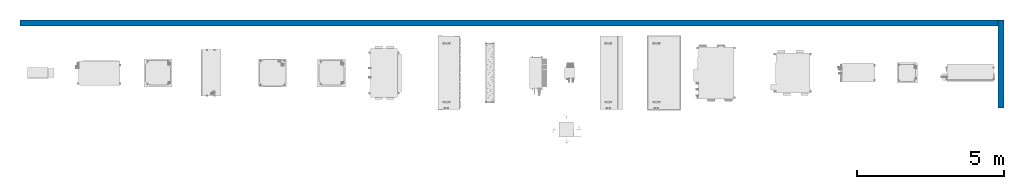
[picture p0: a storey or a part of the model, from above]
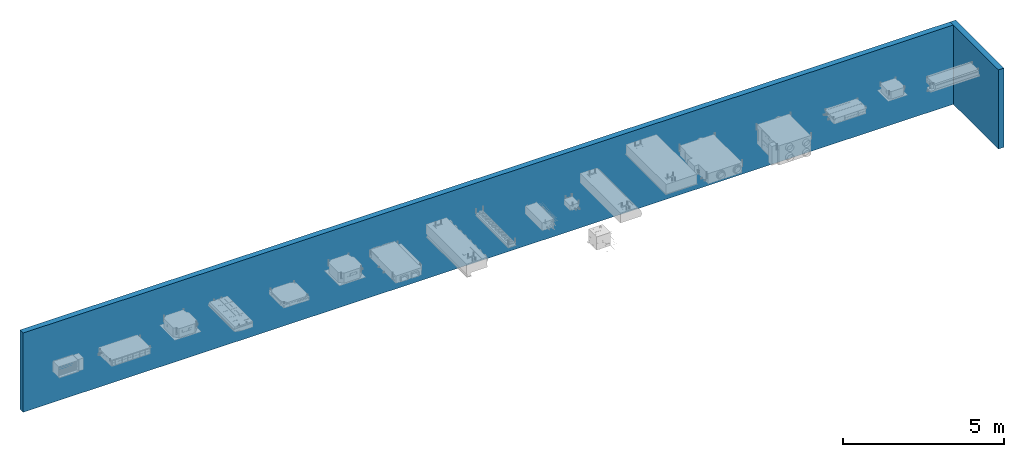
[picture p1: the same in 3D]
Properties of the parts of a building model (IFC2X3), part 1 of 3

# File
Description: ViewDefinition [CoordinationView_V2.0]
Time: 2023-03-29T12:23:49
Written by: The EXPRESS Data Manager Version 5.02.0100.07 : 28 Aug 2013
Made in: 20220224_1700(x64) - Exporter 19.2.60.3 - Default UI
Comment: STEP Physical File produced by: The EXPRESS Data Manager Version 5.02.0100.07 : 28 Aug 2013 * Module: EDMstepFileFactory/EDMstandAlone * Creation date: Wed Mar 29 12:23:49 2023 * Host: DESKTOP-IHH7OF8 * Database: C:\Users\BMP_02\AppData\Local\Temp\{4DC32F8F-CF9E-48E4-9B4F-A92181148DC5}\ifc * Database version: 5507 * Database creation date: Wed Mar 29 12:23:40 2023 * Schema: IFC2X3 * Model: DataRepository.ifc * Model creation date: Wed Mar 29 12:23:41 2023 * Header model: DataRepository.ifc_HeaderModel * Header model creation date: Wed Mar 29 12:23:41 2023 * EDMuser: sdai-user * EDMgroup: sdai-group * License ID and type: 5605 : Permanent license. Expiry date: * EDMstepFileFactory options: 020000

# IfcSite, Default
RefLatitude: 42, 24, 53, 508911; RefLongitude: -71, -15, -29, -58837; RefElevation: 0 mm
Other - Category: Project Information

# IfcBuilding
Pset_BuildingCommon - NumberOfStoreys: 1
Other - Category: Project Information

# IfcBuildingStorey, Level 1
LongName: Level 1; Elevation: 0 mm
Other(Type) - Category: Levels; Family Name: Level
Identity Data(Type) - Type Name: Level 1
Graphics(Type) - Color: 0; Line Pattern: Solid; Line Weight: 1; Symbol at End 1 Default: no; Symbol at End 2 Default: yes
Constraints(Type) - Elevation Base: Project Base Point
Constraints - Elevation: 0 mm
Dimensions - Computation Height: 0 mm
Identity Data - Structural: no; Building Story: yes; Name: Level 1
Other - Category: Levels; Family: Level: Level 1; Family and Type: Level: Level 1; Type: Level: Level 1; Type Id: Level: Level 1

# IfcBuildingElementProxy: reference geometry_gen, RSen_00_GM_FB_reference geometry_gen_witas:reference geometry_gen:1185629
In: Level 1
Type - Material: RSen_x_rgb 255 128 128 T80 red_gen, RSen_x_rgb 255 0 0 T00 red_gen, RSen_x_rgb 255 255 255 T00 pure white_gen, RSen_x_rgb 000 000 000 T00 black_gen, RSen_x_rgb 021 107 182 T00 blue_gen, RSen_x_rgb 000 128 000 T80 green_gen
Type - Constraints - Default Elevation: 0 mm; WT_H Reference_angled wall mounted: angled wall mounted_gen; WT_H Reference_parallel wall mounted: parallel wall mounted_gen; WT_H Reference_pendant - horizontal mounted: pendant - horizontal mounted_gen; WT_H Reference_pendant - vertical mounted: pendant - vertical mounted_gen; WT_H Reference_recessed: recessed_gen; WT_H Reference_wall mounted: wall mounted_gen
Type - Identity Data - Type Name: reference geometry_gen; WT_I Coding: V4.0; WT_I Interface: V4.0
Type - Other - Category: Generic Models; Family Name: RSen_00_GM_FB_reference geometry_gen_witas
Type - Text - 250: 250 mm; WT_I Revit manual: http://revit-mep-be-localiser.blogspot.com/2010/01/referentiebalk.html
Pset_BuildingElementProxyCommon - Reference: reference geometry_gen
Constraints - Elevation: 2500 mm; Host: Reference Plane : ceiling; Level: Level: Level 1; WT_H Depth 1: 500 mm; WT_H Depth 2: 10000 mm; WT_H Half height: 250 mm; WT_H Half height_negative: -250 mm; WT_H Half length: 250 mm; WT_H Half length_negative: -250 mm; WT_H Height: 500 mm; WT_H Length: 500 mm; WT_H Reference_type: pendant - horizontal mounted_gen; WT_H Suspension: yes; WT_H Suspension_height: 1 mm; WT_H X coordinate in plane: 0 mm; WT_H Y coordinate in plane: 0 mm
Construction - WT_V Angled wall mounted: no; WT_V Parallel wall mounted: no; WT_V Pendant - horizontal mounted: yes; WT_V Pendant - vertical mounted: no; WT_V Plane: 1; WT_V Recess depth: 0 mm; WT_V Recessed: no; WT_V Rotation about axis: 0 deg; WT_V Surface mounted: no; WT_V Suspension_height: 0 mm; WT_V X coordinate in plane: 0 mm; WT_V Y coordinate in plane: 0 mm; WT_V Z coordinate in plane: 0.1 mm
Dimensions - Area: 2.52812 m2; Volume: 0.375224 m3
Graphics - Mark: no
Other - Family: RSen_00_GM_FB_reference geometry_gen_witas: reference geometry_gen; Family and Type: RSen_00_GM_FB_reference geometry_gen_witas: reference geometry_gen; Schedule Level: Level: Level 1; Type: RSen_00_GM_FB_reference geometry_gen_witas: reference geometry_gen; Type Id: RSen_00_GM_FB_reference geometry_gen_witas: reference geometry_gen
Phasing - Phase Created: New Construction
Text - Dim_01: L; Dim_02: H; Dim_03: W

# IfcBuildingElementProxy: standard, RSen_57_ME_FB_SOg - alb02rbsnadbt00 - SH_daikin_tbq:standard:1750593
In: Level 1
Type - Material: RSen_n6_PE_black, RSen_x_rgb 199 235 223 T00 galvanised steel plate_gen
Type - Constraints - Default Elevation: 1219.2 mm; TBQ SOg: yes
Type - Dimensions - TBQ Height: 292 mm; TBQ Length: 1820 mm; TBQ Width: 920 mm
Type - Identity Data - Manufacturer: Daikin Europe N.V.; Type Name: standard
Type - Materials and Finishes - TBQ Material 01: RSen_x_rgb 199 235 223 T00 galvanised steel plate_gen; TBQ Material 02: RSen_n6_PE_black
Type - Other - Category: Mechanical Equipment; Family Name: RSen_57_ME_FB_SOg - alb02rbsnadbt00 - SH_daikin_tbq
Pset_BuildingElementProxyCommon - Reference: standard
Pset_ManufacturerTypeInformation - Manufacturer: Daikin Europe N.V.
Constraints - Moves With Nearby Elements: no
Dimensions - Area: 5.74131 m2; Volume: 0.510282 m3
Identity Data - Mark: 113
Other - Family: RSen_57_ME_FB_SOg - alb02rbsnadbt00 - SH_daikin_tbq: standard; Family and Type: RSen_57_ME_FB_SOg - alb02rbsnadbt00 - SH_daikin_tbq: standard; Type: RSen_57_ME_FB_SOg - alb02rbsnadbt00 - SH_daikin_tbq: standard; Type Id: RSen_57_ME_FB_SOg - alb02rbsnadbt00 - SH_daikin_tbq: standard
Phasing - Phase Created: New Construction

# IfcBuildingElementProxy: standard, RSen_57_DUA_FB_SOg - ald07hefbu00 - SH_daikin_tbq:standard:2526252
In: Level 1
Type - Material: RSen_x_rgb 000 000 000 T00 black_gen, RSen_x_rgb 195 195 195 T00 silver_gen
Type - Constraints - Default Elevation: 1219.2 mm; TBQ SOg: yes
Type - Dimensions - TBQ Depth: 440 mm; TBQ Height: 740 mm; TBQ Length: 370 mm
Type - Identity Data - Manufacturer: Daikin Europe N.V.; Type Name: standard
Type - Materials and Finishes - TBQ Material 01: RSen_x_rgb 195 195 195 T00 silver_gen; TBQ Material 02: RSen_x_rgb 000 000 000 T00 black_gen
Type - Other - Category: Duct Accessories; Family Name: RSen_57_DUA_FB_SOg - ald07hefbu00 - SH_daikin_tbq
Pset_BuildingElementProxyCommon - Reference: standard
Pset_ManufacturerTypeInformation - Manufacturer: Daikin Europe N.V.
Constraints - Moves With Nearby Elements: no
Dimensions - Area: 1.96556 m2; Volume: 0.031201 m3
Identity Data - Mark: 3
Insulation - Insulation Thickness: 0 mm
Lining - Lining Thickness: 0 mm
Other - Family: RSen_57_DUA_FB_SOg - ald07hefbu00 - SH_daikin_tbq: standard; Family and Type: RSen_57_DUA_FB_SOg - ald07hefbu00 - SH_daikin_tbq: standard; Type: RSen_57_DUA_FB_SOg - ald07hefbu00 - SH_daikin_tbq: standard; Type Id: RSen_57_DUA_FB_SOg - ald07hefbu00 - SH_daikin_tbq: standard
Phasing - Phase Created: New Construction

# IfcBuildingElementProxy: standard, RSen_55_ME_FB_SOg - fha140aveb - SH_daikin_tbq:standard:2197211
In: Level 1
Type - Material: RSen_x_rgb 055 053 053 T00 gray_gen, RSen_x_rgb 0 0 0 T30 aluminium rectangular canvas_gen, RSen_x_rgb 255 255 255 T00 pure white_gen
Type - Constraints - Default Elevation: 1219.2 mm; TBQ SOg: yes
Type - Dimensions - TBQ Height: 235 mm; TBQ Length: 1590 mm; TBQ Width: 690 mm
Type - Identity Data - Manufacturer: Daikin Europe N.V.; Type Name: standard
Type - Materials and Finishes - TBQ Material 01: RSen_x_rgb 255 255 255 T00 pure white_gen; TBQ Material 02: RSen_x_rgb 0 0 0 T30 aluminium rectangular canvas_gen
Type - Other - Category: Mechanical Equipment; Family Name: RSen_55_ME_FB_SOg - fha140aveb - SH_daikin_tbq
Pset_BuildingElementProxyCommon - Reference: standard
Pset_ManufacturerTypeInformation - Manufacturer: Daikin Europe N.V.
Constraints - Moves With Nearby Elements: no
Dimensions - Area: 2.86119 m2; Volume: 0.144938 m3
Identity Data - Mark: 134
Other - Family: RSen_55_ME_FB_SOg - fha140aveb - SH_daikin_tbq: standard; Family and Type: RSen_55_ME_FB_SOg - fha140aveb - SH_daikin_tbq: standard; Type: RSen_55_ME_FB_SOg - fha140aveb - SH_daikin_tbq: standard; Type Id: RSen_55_ME_FB_SOg - fha140aveb - SH_daikin_tbq: standard
Phasing - Phase Created: New Construction

# IfcBuildingElementProxy: standard, RSen_55_ME_FB_SOg - fcahg71gveb - auto-cleaning panel - SH_daikin_tbq:standard:2167862
In: Level 1
Type - Material: RSen_x_rgb 055 053 053 T00 gray_gen, RSen_x_rgb 244 244 244 T00 aluminium_gen, RSen_x_rgb 255 255 255 T00 pure white_gen
Type - Constraints - Default Elevation: 1219.2 mm; TBQ SOg: yes
Type - Dimensions - TBQ Height: 418 mm; TBQ Length: 950 mm; TBQ Width: 950 mm
Type - Identity Data - Manufacturer: Daikin Europe N.V.; Type Name: standard
Type - Materials and Finishes - TBQ Material 01: RSen_x_rgb 255 255 255 T00 pure white_gen; TBQ Material 02: RSen_x_rgb 244 244 244 T00 aluminium_gen
Type - Other - Category: Mechanical Equipment; Family Name: RSen_55_ME_FB_SOg - fcahg71gveb - auto-cleaning panel - SH_daikin_tbq
Pset_BuildingElementProxyCommon - Reference: standard
Pset_ManufacturerTypeInformation - Manufacturer: Daikin Europe N.V.
Constraints - Moves With Nearby Elements: no
Dimensions - Area: 3.08485 m2; Volume: 0.275474 m3
Identity Data - Mark: 130
Other - Family: RSen_55_ME_FB_SOg - fcahg71gveb - auto-cleaning panel - SH_daikin_tbq: standard; Family and Type: RSen_55_ME_FB_SOg - fcahg71gveb - auto-cleaning panel - SH_daikin_tbq: standard; Type: RSen_55_ME_FB_SOg - fcahg71gveb - auto-cleaning panel - SH_daikin_tbq: standard; Type Id: RSen_55_ME_FB_SOg - fcahg71gveb - auto-cleaning panel - SH_daikin_tbq: standard
Phasing - Phase Created: New Construction

# IfcBuildingElementProxy: standard, RSen_55_ME_FB_SOg - fua71aveb - SH_daikin_tbq:standard:2197208
In: Level 1
Type - Material: RSen_x_rgb 055 053 053 T00 gray_gen, RSen_x_rgb 244 244 244 T00 signal white_gen
Type - Constraints - Default Elevation: 1219.2 mm; TBQ SOg: yes
Type - Dimensions - TBQ Height: 198 mm; TBQ Length: 950 mm; TBQ Width: 950 mm
Type - Identity Data - Manufacturer: Daikin Europe N.V.; Type Name: standard
Type - Materials and Finishes - TBQ Material_01: RSen_x_rgb 244 244 244 T00 signal white_gen
Type - Other - Category: Mechanical Equipment; Family Name: RSen_55_ME_FB_SOg - fua71aveb - SH_daikin_tbq
Pset_BuildingElementProxyCommon - Reference: standard
Pset_ManufacturerTypeInformation - Manufacturer: Daikin Europe N.V.
Constraints - Moves With Nearby Elements: no
Dimensions - Area: 1.64605 m2; Volume: 0.159636 m3
Identity Data - Mark: 133
Other - Family: RSen_55_ME_FB_SOg - fua71aveb - SH_daikin_tbq: standard; Family and Type: RSen_55_ME_FB_SOg - fua71aveb - SH_daikin_tbq: standard; Type: RSen_55_ME_FB_SOg - fua71aveb - SH_daikin_tbq: standard; Type Id: RSen_55_ME_FB_SOg - fua71aveb - SH_daikin_tbq: standard
Phasing - Phase Created: New Construction

# IfcBuildingElementProxy: standard, RSen_55_ME_FB_SOg - fxfn112a2veb - designer panel - SH_daikin_tbq:standard:2414036
In: Level 1
Type - Material: RSen_x_rgb 055 053 053 T00 gray_gen, RSen_x_rgb 255 255 255 T00 pure white_gen, RSen_x_rgb 244 244 244 T00 aluminium_gen
Type - Constraints - Default Elevation: 1219.2 mm; TBQ SOg: yes
Type - Dimensions - TBQ Height: 385 mm; TBQ Length: 950 mm; TBQ Width: 950 mm
Type - Identity Data - Manufacturer: Daikin Europe N.V.; Type Name: standard
Type - Materials and Finishes - TBQ Material 01: RSen_x_rgb 255 255 255 T00 pure white_gen; TBQ Material 02: RSen_x_rgb 244 244 244 T00 aluminium_gen
Type - Other - Category: Mechanical Equipment; Family Name: RSen_55_ME_FB_SOg - fxfn112a2veb - designer panel - SH_daikin_tbq
Pset_BuildingElementProxyCommon - Reference: standard
Pset_ManufacturerTypeInformation - Manufacturer: Daikin Europe N.V.
Constraints - Moves With Nearby Elements: no
Dimensions - Area: 3.19227 m2; Volume: 0.235009 m3
Identity Data - Mark: 157
Other - Family: RSen_55_ME_FB_SOg - fxfn112a2veb - designer panel - SH_daikin_tbq: standard; Family and Type: RSen_55_ME_FB_SOg - fxfn112a2veb - designer panel - SH_daikin_tbq: standard; Type: RSen_55_ME_FB_SOg - fxfn112a2veb - designer panel - SH_daikin_tbq: standard; Type Id: RSen_55_ME_FB_SOg - fxfn112a2veb - designer panel - SH_daikin_tbq: standard
Phasing - Phase Created: New Construction

# IfcBuildingElementProxy: standard, RSen_57_ME_FB_SOg - cyvl250dk250csc - SH_daikin_tbq:standard:1401916
In: Level 1
Type - Material: RSen_x_rgb 165 165 165 T00 white aluminium_gen, RSen_x_rgb 0 0 0 T30 aluminium rectangular canvas_gen
Type - Constraints - Default Elevation: 1219.2 mm; TBQ SOg: yes
Type - Dimensions - TBQ Height: 370 mm; TBQ Length: 2500 mm; TBQ Width: 1105 mm
Type - Identity Data - Manufacturer: Daikin Europe N.V.; Type Name: standard
Type - Materials and Finishes - TBQ Material 01: RSen_x_rgb 165 165 165 T00 white aluminium_gen; TBQ Material 02: RSen_x_rgb 80 80 80 T00 aluminium canvas_gen; TBQ Material 03: RSen_x_rgb 0 0 0 T30 aluminium rectangular canvas_gen
Type - Other - Category: Mechanical Equipment; Family Name: RSen_57_ME_FB_SOg - cyvl250dk250csc - SH_daikin_tbq
Pset_BuildingElementProxyCommon - Reference: standard
Pset_ManufacturerTypeInformation - Manufacturer: Daikin Europe N.V.
Constraints - Moves With Nearby Elements: no
Dimensions - Area: 8.4651 m2; Volume: 0.933752 m3
Identity Data - Mark: 80
Other - Family: RSen_57_ME_FB_SOg - cyvl250dk250csc - SH_daikin_tbq: standard; Family and Type: RSen_57_ME_FB_SOg - cyvl250dk250csc - SH_daikin_tbq: standard; Type: RSen_57_ME_FB_SOg - cyvl250dk250csc - SH_daikin_tbq: standard; Type Id: RSen_57_ME_FB_SOg - cyvl250dk250csc - SH_daikin_tbq: standard
Phasing - Phase Created: New Construction

# IfcBuildingElementProxy: standard, RSen_55_ME_FB_SOg - bs1q25a7v1b - SH_daikin_tbq:standard:1640164
In: Level 1
Type - Material: RSen_x_rgb 199 235 223 T00 galvanised steel plate_gen
Type - Constraints - Default Elevation: 1219.2 mm; TBQ SOg: yes
Type - Dimensions - TBQ Height: 207 mm; TBQ Length: 388 mm; TBQ Width: 326 mm
Type - Identity Data - Manufacturer: Daikin Europe N.V.; Type Name: standard
Type - Materials and Finishes - TBQ Material: RSen_x_rgb 199 235 223 T00 galvanised steel plate_gen
Type - Other - Category: Mechanical Equipment; Family Name: RSen_55_ME_FB_SOg - bs1q25a7v1b - SH_daikin_tbq
Pset_BuildingElementProxyCommon - Reference: standard
Pset_ManufacturerTypeInformation - Manufacturer: Daikin Europe N.V.
Constraints - Moves With Nearby Elements: no
Dimensions - Area: 0.406695 m2; Volume: 0.0254043 m3
Identity Data - Mark: 108
Other - Family: RSen_55_ME_FB_SOg - bs1q25a7v1b - SH_daikin_tbq: standard; Family and Type: RSen_55_ME_FB_SOg - bs1q25a7v1b - SH_daikin_tbq: standard; Type: RSen_55_ME_FB_SOg - bs1q25a7v1b - SH_daikin_tbq: standard; Type Id: RSen_55_ME_FB_SOg - bs1q25a7v1b - SH_daikin_tbq: standard
Phasing - Phase Created: New Construction

# IfcBuildingElementProxy: standard, RSen_55_ME_FB_SOg - bs16q14av1b - SH_daikin_tbq:standard:1639782
In: Level 1
Type - Material: RSen_x_rgb 199 235 223 T00 galvanised steel plate_gen, RSen_n6_PE_black
Type - Constraints - Default Elevation: 1219.2 mm; TBQ SOg: yes
Type - Dimensions - TBQ Height: 298 mm; TBQ Length: 1060 mm; TBQ Width: 430 mm
Type - Identity Data - Manufacturer: Daikin Europe N.V.; Type Name: standard
Type - Materials and Finishes - TBQ Material 01: RSen_x_rgb 199 235 223 T00 galvanised steel plate_gen; TBQ Material 02: RSen_n6_PE_black
Type - Other - Category: Mechanical Equipment; Family Name: RSen_55_ME_FB_SOg - bs16q14av1b - SH_daikin_tbq
Pset_BuildingElementProxyCommon - Reference: standard
Pset_ManufacturerTypeInformation - Manufacturer: Daikin Europe N.V.
Constraints - Moves With Nearby Elements: no
Dimensions - Area: 2.23692 m2; Volume: 0.138375 m3
Identity Data - Mark: 107
Other - Family: RSen_55_ME_FB_SOg - bs16q14av1b - SH_daikin_tbq: standard; Family and Type: RSen_55_ME_FB_SOg - bs16q14av1b - SH_daikin_tbq: standard; Type: RSen_55_ME_FB_SOg - bs16q14av1b - SH_daikin_tbq: standard; Type Id: RSen_55_ME_FB_SOg - bs16q14av1b - SH_daikin_tbq: standard
Phasing - Phase Created: New Construction

# IfcBuildingElementProxy: standard, RSen_57_ME_FB_SOg - vkm100gbmv1 - SH_daikin_tbq:standard:1596971
In: Level 1
Type - Material: RSen_x_rgb 199 235 223 T00 galvanised steel plate_gen, RSen_n6_PE_black
Type - Constraints - Default Elevation: 1219.2 mm; TBQ SOg: yes
Type - Dimensions - TBQ Height: 387 mm; TBQ Length: 1764 mm; TBQ Width: 1214 mm
Type - Identity Data - Manufacturer: Daikin Europe N.V.; Type Name: standard
Type - Materials and Finishes - TBQ Material 01: RSen_x_rgb 199 235 223 T00 galvanised steel plate_gen; TBQ Material 02: RSen_n6_PE_black
Type - Other - Category: Mechanical Equipment; Family Name: RSen_57_ME_FB_SOg - vkm100gbmv1 - SH_daikin_tbq
Pset_BuildingElementProxyCommon - Reference: standard
Pset_ManufacturerTypeInformation - Manufacturer: Daikin Europe N.V.
Constraints - Moves With Nearby Elements: no
Dimensions - Area: 4.55629 m2; Volume: 0.860185 m3
Identity Data - Mark: 106
Other - Family: RSen_57_ME_FB_SOg - vkm100gbmv1 - SH_daikin_tbq: standard; Family and Type: RSen_57_ME_FB_SOg - vkm100gbmv1 - SH_daikin_tbq: standard; Type: RSen_57_ME_FB_SOg - vkm100gbmv1 - SH_daikin_tbq: standard; Type Id: RSen_57_ME_FB_SOg - vkm100gbmv1 - SH_daikin_tbq: standard
Phasing - Phase Created: New Construction

# IfcBuildingElementProxy: standard, RSen_57_ME_FB_SOg - vam1500j8veb - SH_daikin_tbq:standard:1594922
In: Level 1
Type - Material: RSen_x_rgb 199 235 223 T00 galvanised steel plate_gen, RSen_n6_PE_black
Type - Constraints - Default Elevation: 1219.2 mm; TBQ SOg: yes
Type - Dimensions - TBQ Height: 731 mm; TBQ Length: 1354 mm; TBQ Width: 1170 mm
Type - Identity Data - Manufacturer: Daikin Europe N.V.; Type Name: standard
Type - Materials and Finishes - TBQ Material 01: RSen_x_rgb 199 235 223 T00 galvanised steel plate_gen; TBQ Material 02: RSen_n6_PE_black
Type - Other - Category: Mechanical Equipment; Family Name: RSen_57_ME_FB_SOg - vam1500j8veb - SH_daikin_tbq
Pset_BuildingElementProxyCommon - Reference: standard
Pset_ManufacturerTypeInformation - Manufacturer: Daikin Europe N.V.
Constraints - Moves With Nearby Elements: no
Dimensions - Area: 9.30397 m2; Volume: 1.84505 m3
Identity Data - Mark: 105
Other - Family: RSen_57_ME_FB_SOg - vam1500j8veb - SH_daikin_tbq: standard; Family and Type: RSen_57_ME_FB_SOg - vam1500j8veb - SH_daikin_tbq: standard; Type: RSen_57_ME_FB_SOg - vam1500j8veb - SH_daikin_tbq: standard; Type Id: RSen_57_ME_FB_SOg - vam1500j8veb - SH_daikin_tbq: standard
Phasing - Phase Created: New Construction

# IfcBuildingElementProxy: standard, RSen_55_ME_FB_SOg - fxsn112a2veb - SH_daikin_tbq:standard:2485938
In: Level 1
Type - Material: RSen_x_rgb 199 235 223 T00 galvanised steel plate_gen, RSen_n6_PE_black, RSen_x_rgb 80 80 80 T00 aluminium canvas_gen
Type - Constraints - Default Elevation: 1219.2 mm; TBQ SOg: yes
Type - Dimensions - TBQ Height: 245 mm; TBQ Length: 1400 mm; TBQ Width: 800 mm
Type - Identity Data - Manufacturer: Daikin Europe N.V.; Type Name: standard
Type - Materials and Finishes - TBQ Material 01: RSen_x_rgb 199 235 223 T00 galvanised steel plate_gen; TBQ Material 02: RSen_x_rgb 80 80 80 T00 aluminium canvas_gen; TBQ Material 03: RSen_n6_PE_black
Type - Other - Category: Mechanical Equipment; Family Name: RSen_55_ME_FB_SOg - fxsn112a2veb - SH_daikin_tbq
Pset_BuildingElementProxyCommon - Reference: standard
Pset_ManufacturerTypeInformation - Manufacturer: Daikin Europe N.V.
Constraints - Moves With Nearby Elements: no
Dimensions - Area: 3.10641 m2; Volume: 0.231292 m3
Identity Data - Mark: 159
Other - Family: RSen_55_ME_FB_SOg - fxsn112a2veb - SH_daikin_tbq: standard; Family and Type: RSen_55_ME_FB_SOg - fxsn112a2veb - SH_daikin_tbq: standard; Type: RSen_55_ME_FB_SOg - fxsn112a2veb - SH_daikin_tbq: standard; Type Id: RSen_55_ME_FB_SOg - fxsn112a2veb - SH_daikin_tbq: standard
Phasing - Phase Created: New Construction

# IfcBuildingElementProxy: standard, RSen_55_ME_FB_SOg - fwe10c5tv1b - left - SH_daikin_tbq:standard:1868414
In: Level 1
Type - Material: RSen_x_rgb 199 235 223 T00 galvanised steel plate_gen, RSen_x_rgb 80 80 80 T00 aluminium canvas_gen, RSen_n6_PE_black, RSen_x_rgb 72 45 20 T00 copper_gen
Type - Constraints - Default Elevation: 1219.2 mm; TBQ SOg: yes
Type - Dimensions - TBQ Height: 247 mm; TBQ Length: 1780 mm; TBQ Width: 590 mm
Type - Identity Data - Manufacturer: Daikin Europe N.V.; Type Name: standard
Type - Materials and Finishes - TBQ Material 01: RSen_x_rgb 199 235 223 T00 galvanised steel plate_gen; TBQ Material 02: RSen_n6_PE_black; TBQ Material 03: RSen_x_rgb 80 80 80 T00 aluminium canvas_gen; TBQ Material 04: RSen_x_rgb 72 45 20 T00 copper_gen
Type - Other - Category: Mechanical Equipment; Family Name: RSen_55_ME_FB_SOg - fwe10c5tv1b - left - SH_daikin_tbq
Pset_BuildingElementProxyCommon - Reference: standard
Pset_ManufacturerTypeInformation - Manufacturer: Daikin Europe N.V.
Constraints - Moves With Nearby Elements: no
Dimensions - Area: 2.36604 m2; Volume: 0.224428 m3
Identity Data - Mark: 120
Other - Family: RSen_55_ME_FB_SOg - fwe10c5tv1b - left - SH_daikin_tbq: standard; Family and Type: RSen_55_ME_FB_SOg - fwe10c5tv1b - left - SH_daikin_tbq: standard; Type: RSen_55_ME_FB_SOg - fwe10c5tv1b - left - SH_daikin_tbq: standard; Type Id: RSen_55_ME_FB_SOg - fwe10c5tv1b - left - SH_daikin_tbq: standard
Phasing - Phase Created: New Construction

# IfcBuildingElementProxy: standard, RSen_55_ME_FB_SOg - fdxm60f3v1b9 - SH_daikin_tbq:standard:2335656
In: Level 1
Type - Material: RSen_x_rgb 244 244 244 T00 aluminium_gen, RSen_x_rgb 80 80 80 T00 aluminium canvas_gen
Type - Constraints - Default Elevation: 1219.2 mm; TBQ SOg: yes
Type - Dimensions - TBQ Height: 200 mm; TBQ Length: 1150 mm; TBQ Width: 620 mm
Type - Identity Data - Manufacturer: Daikin Europe N.V.; Type Name: standard
Type - Materials and Finishes - TBQ Material 01: RSen_x_rgb 244 244 244 T00 aluminium_gen; TBQ Material 02: RSen_x_rgb 80 80 80 T00 aluminium canvas_gen
Type - Other - Category: Mechanical Equipment; Family Name: RSen_55_ME_FB_SOg - fdxm60f3v1b9 - SH_daikin_tbq
Pset_BuildingElementProxyCommon - Reference: standard
Pset_ManufacturerTypeInformation - Manufacturer: Daikin Europe N.V.
Constraints - Moves With Nearby Elements: no
Dimensions - Area: 2.02584 m2; Volume: 0.130002 m3
Identity Data - Mark: 141
Other - Family: RSen_55_ME_FB_SOg - fdxm60f3v1b9 - SH_daikin_tbq: standard; Family and Type: RSen_55_ME_FB_SOg - fdxm60f3v1b9 - SH_daikin_tbq: standard; Type: RSen_55_ME_FB_SOg - fdxm60f3v1b9 - SH_daikin_tbq: standard; Type Id: RSen_55_ME_FB_SOg - fdxm60f3v1b9 - SH_daikin_tbq: standard
Phasing - Phase Created: New Construction

# IfcBuildingElementProxy: standard, RSen_55_ME_FB_SOg - fwf05b5tv1b - SH_daikin_tbq:standard:2387533
In: Level 1
Type - Material: RSen_x_rgb 244 244 244 T00 signal white_gen, RSen_n6_PE_black, RSen_x_rgb 199 235 223 T00 galvanised steel plate_gen
Type - Constraints - Default Elevation: 1219.2 mm; TBQ SOg: yes
Type - Dimensions - TBQ Height: 315 mm; TBQ Length: 700 mm; TBQ Width: 700 mm
Type - Identity Data - Manufacturer: Daikin Europe N.V.; Type Name: standard
Type - Materials and Finishes - TBQ Material 01: RSen_x_rgb 244 244 244 T00 signal white_gen; TBQ Material 02: RSen_n6_PE_black; TBQ Material 03: RSen_x_rgb 199 235 223 T00 galvanised steel plate_gen
Type - Other - Category: Mechanical Equipment; Family Name: RSen_55_ME_FB_SOg - fwf05b5tv1b - SH_daikin_tbq
Pset_BuildingElementProxyCommon - Reference: standard
Pset_ManufacturerTypeInformation - Manufacturer: Daikin Europe N.V.
Constraints - Moves With Nearby Elements: no
Dimensions - Area: 1.5154 m2; Volume: 0.0992006 m3
Identity Data - Mark: 155
Other - Family: RSen_55_ME_FB_SOg - fwf05b5tv1b - SH_daikin_tbq: standard; Family and Type: RSen_55_ME_FB_SOg - fwf05b5tv1b - SH_daikin_tbq: standard; Type: RSen_55_ME_FB_SOg - fwf05b5tv1b - SH_daikin_tbq: standard; Type Id: RSen_55_ME_FB_SOg - fwf05b5tv1b - SH_daikin_tbq: standard
Phasing - Phase Created: New Construction

# IfcBuildingElementProxy: standard, RSen_57_ME_FB_SOg - cyql250dk250rbn - SH_daikin_tbq:standard:1429487
In: Level 1
Type - Material: RSen_x_rgb 255 255 255 T00 pure white_gen, RSen_x_rgb 0 0 0 T30 aluminium rectangular canvas_gen
Type - Constraints - Default Elevation: 1219.2 mm; TBQ SOg: yes
Type - Dimensions - TBQ Height: 495 mm; TBQ Length: 2500 mm; TBQ Width: 745 mm
Type - Identity Data - Manufacturer: Daikin Europe N.V.; Type Name: standard
Type - Materials and Finishes - TBQ Material 01: RSen_x_rgb 255 255 255 T00 pure white_gen; TBQ Material 02: RSen_x_rgb 0 0 0 T30 aluminium rectangular canvas_gen
Type - Other - Category: Mechanical Equipment; Family Name: RSen_57_ME_FB_SOg - cyql250dk250rbn - SH_daikin_tbq
Pset_BuildingElementProxyCommon - Reference: standard
Pset_ManufacturerTypeInformation - Manufacturer: Daikin Europe N.V.
Constraints - Moves With Nearby Elements: no
Dimensions - Area: 4.61087 m2; Volume: 0.722322 m3
Identity Data - Mark: 83
Other - Family: RSen_57_ME_FB_SOg - cyql250dk250rbn - SH_daikin_tbq: standard; Family and Type: RSen_57_ME_FB_SOg - cyql250dk250rbn - SH_daikin_tbq: standard; Type: RSen_57_ME_FB_SOg - cyql250dk250rbn - SH_daikin_tbq: standard; Type Id: RSen_57_ME_FB_SOg - cyql250dk250rbn - SH_daikin_tbq: standard
Phasing - Phase Created: New Construction

# IfcBuildingElementProxy: standard, RSen_57_ME_FB_SOg - cyvl250dk250fsc - SH_daikin_tbq:standard:1401773
In: Level 1
Type - Material: RSen_x_rgb 80 80 80 T00 aluminium canvas_gen, RSen_x_rgb 165 165 165 T00 white aluminium_gen, RSen_x_rgb 0 0 0 T30 aluminium rectangular canvas_gen
Type - Constraints - Default Elevation: 1219.2 mm; TBQ SOg: yes
Type - Dimensions - TBQ Height: 370 mm; TBQ Length: 2500 mm; TBQ Width: 774 mm
Type - Identity Data - Manufacturer: Daikin Europe N.V.; Type Name: standard
Type - Materials and Finishes - TBQ Material 01: RSen_x_rgb 165 165 165 T00 white aluminium_gen; TBQ Material 02: RSen_x_rgb 80 80 80 T00 aluminium canvas_gen; TBQ Material 03: RSen_x_rgb 0 0 0 T30 aluminium rectangular canvas_gen
Type - Other - Category: Mechanical Equipment; Family Name: RSen_57_ME_FB_SOg - cyvl250dk250fsc - SH_daikin_tbq
Pset_BuildingElementProxyCommon - Reference: standard
Pset_ManufacturerTypeInformation - Manufacturer: Daikin Europe N.V.
Constraints - Moves With Nearby Elements: no
Dimensions - Area: 6.68776 m2; Volume: 0.64305 m3
Identity Data - Mark: 78
Other - Family: RSen_57_ME_FB_SOg - cyvl250dk250fsc - SH_daikin_tbq: standard; Family and Type: RSen_57_ME_FB_SOg - cyvl250dk250fsc - SH_daikin_tbq: standard; Type: RSen_57_ME_FB_SOg - cyvl250dk250fsc - SH_daikin_tbq: standard; Type Id: RSen_57_ME_FB_SOg - cyvl250dk250fsc - SH_daikin_tbq: standard
Phasing - Phase Created: New Construction

# IfcEnergyConversionDevice: alb02rbsnadbt00 - air handling unit - right_daikin_lxwxh 1820x920x292 mm, RSen_57_ME_FB_air handling unit - modular - l_daikin:alb02rbsnadbt00 - air handling unit - right_daikin_lxwxh 1820x920x292 mm:1747594
In: Level 1
Type - PredefinedType: AIRHANDLER; Classification: 57.10.10.10 (Uniformat); Material: RSen_x_rgb 255 255 255 T00 pure white_gen
Type - Constraints - Default Elevation: 0 mm
Type - Construction - TBQen_C_diameter_type_index: 1; TBQen_C_SOg_ME_02: standard; TBQen_C_diameter_type: OD; TBQen_C_SOg_ME_01: RSen_57_ME_FB_SOg - alb02rbsnadbt00 - SH_daikin_tbq: standard
Type - Dimensions - RSen_C_height: 292 mm; RSen_C_length: 1820 mm; RSen_C_width: 920 mm
Type - Electrical - RSen_E_c01_division_engine: no; RSen_E_c01_load_class: Other; RSen_E_c01_number_of_poles: 1; TBQen_E_c01_power_factor: 1; RSen_E_c01_apparent_power: 120 W; RSen_E_c01_current: 0 A; RSen_E_c01_voltage: 230 V; TBQen_E_c01_power: 120 W
Type - Identity Data - Assembly Code: 57.10.10.10; Description: Ventilation; Manufacturer: Daikin Europe N.V.; Model: Modular L; OmniClass Number: 23.75.35.14; OmniClass Title: Air Handling Units; RSen_C_code_article: ALB02RBSNADBT00; RSen_C_code_ETIM: Ventilation appliance; RSen_C_code_ETIM_URL: https://prod.etim-international.com/Class/Details?classId=EC000267&classVersion=5; RSen_C_code_gtin: -; RSen_C_code_product_class: ALB-RBS; RSen_C_content_creator: © ThorbiQ; RSen_C_content_date_changed: 14/01/2021; RSen_C_content_date_issue: 14/01/2021; RSen_C_content_provider: Daikin Europe N.V.; RSen_C_content_version: 2.0.0; RSen_C_description: Ventilation; RSen_C_model: Modular L; RSen_C_revit_version: 2018; RSen_C_type: Air handling unit - right; RSen_C_type_comments: Indoor Unit; TBQ_I BaseKeynote: 57.10.10.10; TBQen_C_code_product: ALB02RBS; TBQen_C_IFC_version: 2x3; TBQen_C_license: Creative Commons Attribution NoDerivs (CC-ND); TBQen_C_license_info: https://tldrlegal.com/license/creative-commons-attribution-noderivs-(cc-nd)#summary; Type Comments: Indoor Unit; Type Name: alb02rbsnadbt00 - air handling unit - right_daikin_lxwxh 1820x920x292 mm; URL: www.daikineurope.com
Type - Materials and Finishes - RSen_C_material: RSen_x_rgb 255 255 255 T00 pure white_gen
Type - Mechanical - RSen_P_c01_load_value: 0; RSen_P_c02_load_value: 0; TBQ_I Air flow rate_speed 1: 0 m3/s; TBQ_I Air flow rate_speed 2: 2.94289 m3/s; TBQ_I Air flow rate_speed 3: 0 m3/s
Type - Model Properties - TBQen_C_mounting_ceiling: yes; TBQen_C_mounting_floor: no; TBQen_C_mounting_wall: no
Type - Other - Category: Mechanical Equipment; TBQen_E_c01_yes_no: yes; TBQen_E_c02_yes_no: yes; TBQen_P_c01_yes_no: yes; TBQen_P_c02_yes_no: yes; TBQen_M_c01_yes_no: yes; TBQen_M_c02_yes_no: yes; TBQen_M_c03_yes_no: yes; TBQen_M_c04_yes_no: yes; Family Name: RSen_57_ME_FB_air handling unit - modular - l_daikin; RSen_E_c01_description: c01_el; RSen_E_c02_description: c02_controls; RSen_M_c01_description: c01_fresh air_outdoor; RSen_M_c01_diameter: 0 mm; RSen_M_c01_height: 150 mm; RSen_M_c01_width: 250 mm; RSen_M_c02_description: c02_exhaust air; RSen_M_c02_diameter: 0 mm; RSen_M_c02_height: 150 mm; RSen_M_c02_width: 250 mm; RSen_M_c03_description: c03_supply air; RSen_M_c03_diameter: 0 mm; RSen_M_c03_height: 150 mm; RSen_M_c03_width: 250 mm; RSen_M_c04_description: c04_return air; RSen_M_c04_diameter: 0 mm; RSen_M_c04_height: 150 mm; RSen_M_c04_width: 250 mm; RSen_P_c01_description: c01_drain piping connection; RSen_P_c01_diameter: 8 mm; RSen_P_c02_description: c02_drain piping connection; RSen_P_c02_diameter: 8 mm; TBQen_E_c01_power_factor_state: Lagging; TBQen_E_c01_system_type: Power - Balanced; TBQen_M_c01_flow_configuration: Preset; TBQen_M_c01_flow_direction: In; TBQen_M_c01_loss_method: Not Defined; TBQen_M_c01_shape: Round; TBQen_M_c01_system_classification: Supply Air; TBQen_M_c02_flow_configuration: Preset; TBQen_M_c02_flow_direction: Out; TBQen_M_c02_loss_method: Not Defined; TBQen_M_c02_shape: Round; TBQen_M_c02_system_classification: Exhaust Air; TBQen_M_c03_flow_configuration: Preset; TBQen_M_c03_flow_direction: Out; TBQen_M_c03_loss_method: Not Defined; TBQen_M_c03_shape: Round; TBQen_M_c03_system_classification: Supply Air; TBQen_M_c04_flow_configuration: Preset; TBQen_M_c04_flow_direction: In; TBQen_M_c04_loss_method: Not Defined; TBQen_M_c04_shape: Round; TBQen_M_c04_system_classification: Return Air; TBQen_P_c01_diameter_calc: 8 mm; TBQen_P_c01_flow_configuration: Fixture Units; TBQen_P_c01_flow_direction: Out; TBQen_P_c01_loss_method: Not Defined; TBQen_P_c01_system_classification: Sanitary; TBQen_P_c02_diameter_calc: 8 mm; TBQen_P_c02_flow_configuration: Fixture Units; TBQen_P_c02_flow_direction: Out; TBQen_P_c02_loss_method: Not Defined; TBQen_P_c02_system_classification: Sanitary
Pset_ManufacturerTypeInformation - Manufacturer: Daikin Europe N.V.
Pset_DistributionFlowElementCommon - Reference: alb02rbsnadbt00 - air handling unit - right_daikin_lxwxh 1820x920x292 mm
Constraints - Level: Level: Level 1; Elevation: 2500 mm; Host: Reference Plane : ceiling
Construction - TBQen_C_alignment_index: 0; TBQen_C_GOg: no; TBQen_C_SOg: yes; TBQen_C_alignment: Center; TBQen_C_suspension_height: 50 mm
Dimensions - Area: 52.6479 m2; Volume: 10.2448 m3
Graphics - TBQen_C_clearance_zone: no; TBQen_C_connection_zone: no; TBQen_C_logo: no; TBQen_C_maintenance_zone: no; TBQen_C_neighbour_unit: no; TBQen_C_neighbour_unit_displacement_back: 0 mm; TBQen_C_neighbour_unit_displacement_front: 0 mm; TBQen_C_neighbour_unit_displacement_left: 0 mm; TBQen_C_neighbour_unit_displacement_right: 0 mm
Identity Data - Mark: 111
Mechanical - RSen_M_c01_flow_rate: 0 m3/s; RSen_M_c02_flow_rate: 0 m3/s; RSen_M_c03_flow_rate: 0 m3/s; RSen_M_c04_flow_rate: 0 m3/s; System Classification: Sanitary,Return Air,Supply Air,Exhaust Air,Power,Controls
Mechanical - Flow - TBQen_M_flow_rate_index: 0; TBQen_M_flow_rate: 0 m3/s; TBQen_M_flow_rate_info: Low
Other - Schedule Level: Level: Level 1; ZZZ_V P_c01_plane_Integer: 4; Family: RSen_57_ME_FB_air handling unit - modular - l_daikin: alb02rbsnadbt00 - air handling unit - right_daikin_lxwxh 1820x920x292 mm; Family and Type: RSen_57_ME_FB_air handling unit - modular - l_daikin: alb02rbsnadbt00 - air handling unit - right_daikin_lxwxh 1820x920x292 mm; Type: RSen_57_ME_FB_air handling unit - modular - l_daikin: alb02rbsnadbt00 - air handling unit - right_daikin_lxwxh 1820x920x292 mm; Type Id: RSen_57_ME_FB_air handling unit - modular - l_daikin: alb02rbsnadbt00 - air handling unit - right_daikin_lxwxh 1820x920x292 mm; ZZZ_V P_c01_X_Length: -157.5 mm; ZZZ_V P_c01_Y_Length: 108 mm
Phasing - Phase Created: New Construction
Text - RSen_C_content_manual: https://thorbiq.freshdesk.com/support/solutions

# IfcEnergyConversionDevice: cyql250dk250rbn - large - white_daikin_lxwxh 2548x745x495 mm, RSen_57_ME_FB_air curtain - 8 connections_daikin:cyql250dk250rbn - large - white_daikin_lxwxh 2548x745x495 mm:1402082
In: Level 1
Type - PredefinedType: AIRHANDLER; Classification: 57.10.10.20 (Uniformat); Material: RSen_x_rgb 255 255 255 T00 pure white_gen
Type - Constraints - Default Elevation: 0 mm
Type - Construction - TBQen_C_diameter_type_index: 1; TBQen_C_SOg_ME_02: standard; TBQen_C_diameter_type: OD; TBQen_C_SOg_ME_01: RSen_57_ME_FB_SOg - cyql250dk250rbn - SH_daikin_tbq: standard
Type - Dimensions - RSen_C_height: 495 mm; RSen_C_length: 2548 mm; RSen_C_width: 745 mm
Type - Electrical - RSen_E_c01_division_engine: no; RSen_E_c01_load_class: Other; RSen_E_c01_number_of_poles: 1; TBQen_E_c01_power_factor: 1; RSen_E_c01_apparent_power: 1880 W; RSen_E_c01_current: 0 A; RSen_E_c01_voltage: 230 V; TBQen_E_c01_power: 1880 W
Type - Identity Data - Assembly Code: 57.10.10.20; Description: Heat Pump; Manufacturer: Daikin Europe N.V.; Model: Air Curtain; OmniClass Number: 23.75.35.17.21; OmniClass Title: Air Curtains; RSen_C_code_article: CYQL250DK250RBN; RSen_C_code_ETIM: Air curtain for cold application; RSen_C_code_ETIM_URL: https://prod.etim-international.com/Class/Details?classId=EC011450&classVersion=4; RSen_C_code_gtin: -; RSen_C_code_product_class: CYQL-DK-R; RSen_C_content_creator: © ThorbiQ; RSen_C_content_date_changed: 14/01/2021; RSen_C_content_date_issue: 14/01/2021; RSen_C_content_provider: Daikin Europe N.V.; RSen_C_content_version: 2.0.0; RSen_C_description: Heat Pump; RSen_C_description_01: Large - white; RSen_C_description_02: Recessed; RSen_C_model: Air Curtain; RSen_C_revit_version: 2018; RSen_C_type: Air curtain, concealed ceiling; RSen_C_type_comments: Air Curtain; TBQ_I BaseKeynote: 57.10.10.20; TBQen_C_code_product: CYQL250DK250RBN; TBQen_C_IFC_version: 2x3; TBQen_C_license: Creative Commons Attribution NoDerivs (CC-ND); TBQen_C_license_info: https://tldrlegal.com/license/creative-commons-attribution-noderivs-(cc-nd)#summary; Type Comments: Air Curtain; Type Name: cyql250dk250rbn - large - white_daikin_lxwxh 2548x745x495 mm; URL: www.daikineurope.com
Type - Materials and Finishes - RSen_C_material: RSen_x_rgb 255 255 255 T00 pure white_gen
Type - Mechanical - RSen_P_c01_volume_flow: 0 m3/s; RSen_P_c02_volume_flow: 0 m3/s; TBQ_I Air flow rate_speed 1: 0 m3/s; TBQ_I Air flow rate_speed 2: 0.0504215 m3/s; TBQ_I Air flow rate_speed 3: 0.0760246 m3/s
Type - Model Properties - TBQen_C_mounting_ceiling: yes; TBQen_C_mounting_floor: no; TBQen_C_mounting_wall: no
Type - Other - Category: Mechanical Equipment; TBQen_E_c01_yes_no: yes; TBQen_E_c02_yes_no: yes; TBQen_P_c01_yes_no: yes; TBQen_P_c02_yes_no: yes; RSen_M_c01_height: 0 mm; RSen_M_c01_width: 0 mm; RSen_M_c02_height: 0 mm; RSen_M_c02_width: 0 mm; RSen_M_c03_height: 0 mm; RSen_M_c03_width: 0 mm; RSen_M_c04_height: 0 mm; RSen_M_c04_width: 0 mm; RSen_M_c05_height: 0 mm; RSen_M_c05_width: 0 mm; RSen_M_c06_height: 0 mm; RSen_M_c06_width: 0 mm; RSen_M_c07_height: 0 mm; RSen_M_c07_width: 0 mm; RSen_M_c08_height: 0 mm; RSen_M_c08_width: 0 mm; TBQen_M_c01_yes_no: yes; TBQen_M_c02_yes_no: yes; TBQen_M_c03_yes_no: yes; TBQen_M_c04_yes_no: yes; TBQen_M_c05_yes_no: yes; TBQen_M_c06_yes_no: yes; TBQen_M_c07_yes_no: yes; TBQen_M_c08_yes_no: yes; Family Name: RSen_57_ME_FB_air curtain - 8 connections_daikin; RSen_E_c01_description: c01_el; RSen_E_c02_description: c02_controls; RSen_M_c01_description: c01_fitting; RSen_M_c01_diameter: 250 mm; RSen_M_c02_description: c02_fitting; RSen_M_c02_diameter: 250 mm; RSen_M_c03_description: c03_fitting; RSen_M_c03_diameter: 250 mm; RSen_M_c04_description: c04_fitting; RSen_M_c04_diameter: 250 mm; RSen_M_c05_description: c05_fitting; RSen_M_c05_diameter: 250 mm; RSen_M_c06_description: c06_fitting; RSen_M_c06_diameter: 250 mm; RSen_M_c07_description: c07_fitting; RSen_M_c07_diameter: 250 mm; RSen_M_c08_description: c08_fitting; RSen_M_c08_diameter: 250 mm; RSen_P_c01_description: c01_liquid piping connection; RSen_P_c01_diameter: 9.52 mm; RSen_P_c02_description: c02_gas piping connection; RSen_P_c02_diameter: 22 mm; TBQen_E_c01_power_factor_state: Lagging; TBQen_E_c01_system_type: Power - Balanced; TBQen_M_c01_flow_configuration: -; TBQen_M_c01_flow_direction: In; TBQen_M_c01_loss_method: Not Defined; TBQen_M_c01_shape: Round; TBQen_M_c01_system_classification: Fitting; TBQen_M_c02_flow_configuration: -; TBQen_M_c02_flow_direction: In; TBQen_M_c02_loss_method: Not Defined; TBQen_M_c02_shape: Round; TBQen_M_c02_system_classification: Fitting; TBQen_M_c03_flow_configuration: -; TBQen_M_c03_flow_direction: In; TBQen_M_c03_loss_method: Not Defined; TBQen_M_c03_shape: Round; TBQen_M_c03_system_classification: Fitting; TBQen_M_c04_flow_configuration: -; TBQen_M_c04_flow_direction: In; TBQen_M_c04_loss_method: Not Defined; TBQen_M_c04_shape: Round; TBQen_M_c04_system_classification: Fitting; TBQen_M_c05_flow_configuration: -; TBQen_M_c05_flow_direction: In; TBQen_M_c05_loss_method: Not Defined; TBQen_M_c05_shape: Round; TBQen_M_c05_system_classification: Fitting; TBQen_M_c06_flow_configuration: -; TBQen_M_c06_flow_direction: In; TBQen_M_c06_loss_method: Not Defined; TBQen_M_c06_shape: Round; TBQen_M_c06_system_classification: Fitting; TBQen_M_c07_flow_configuration: -; TBQen_M_c07_flow_direction: In; TBQen_M_c07_loss_method: Not Defined; TBQen_M_c07_shape: Round; TBQen_M_c07_system_classification: Fitting; TBQen_M_c08_flow_configuration: -; TBQen_M_c08_flow_direction: In; TBQen_M_c08_loss_method: Not Defined; TBQen_M_c08_shape: Round; TBQen_M_c08_system_classification: Fitting; TBQen_P_c01_diameter_calc: 9.5 mm; TBQen_P_c01_flow_configuration: Preset; TBQen_P_c01_flow_direction: In; TBQen_P_c01_loss_method: Not Defined; TBQen_P_c01_system_classification: Hydronic Supply; TBQen_P_c02_diameter_calc: 22 mm; TBQen_P_c02_flow_configuration: Preset; TBQen_P_c02_flow_direction: Out; TBQen_P_c02_loss_method: Not Defined; TBQen_P_c02_system_classification: Hydronic Return
Pset_ManufacturerTypeInformation - Manufacturer: Daikin Europe N.V.
Pset_DistributionFlowElementCommon - Reference: cyql250dk250rbn - large - white_daikin_lxwxh 2548x745x495 mm
Constraints - Level: Level: Level 1; Elevation: 2500 mm; Host: Reference Plane : ceiling
Construction - TBQen_C_alignment_index: 0; TBQen_C_GOg: no; TBQen_C_SOg: yes; TBQen_C_alignment: Center; TBQen_C_suspension_height: 150 mm
Dimensions - Area: 89.6465 m2; Volume: 23.5312 m3
Graphics - TBQen_C_clearance_zone: no; TBQen_C_connection_zone: no; TBQen_C_logo: no; TBQen_C_maintenance_zone: no; TBQen_C_neighbour_unit: no; TBQen_C_neighbour_unit_displacement_back: 0 mm; TBQen_C_neighbour_unit_displacement_front: 0 mm; TBQen_C_neighbour_unit_displacement_left: 0 mm; TBQen_C_neighbour_unit_displacement_right: 0 mm
Identity Data - Mark: 81
Mechanical - System Classification: Hydronic Return,Hydronic Supply,Undefined,Power,Undefined,Controls
Mechanical - Flow - TBQen_M_flow_rate_index: 2; TBQen_M_flow_rate: 0.0760246 m3/s; TBQen_M_flow_rate_info: Speed 3
Other - Schedule Level: Level: Level 1; Family: RSen_57_ME_FB_air curtain - 8 connections_daikin: cyql250dk250rbn - large - white_daikin_lxwxh 2548x745x495 mm; Family and Type: RSen_57_ME_FB_air curtain - 8 connections_daikin: cyql250dk250rbn - large - white_daikin_lxwxh 2548x745x495 mm; Type: RSen_57_ME_FB_air curtain - 8 connections_daikin: cyql250dk250rbn - large - white_daikin_lxwxh 2548x745x495 mm; Type Id: RSen_57_ME_FB_air curtain - 8 connections_daikin: cyql250dk250rbn - large - white_daikin_lxwxh 2548x745x495 mm; ZZZ_V M_c01_plane_Integer: 3; ZZZ_V M_c01_X_Length: 1070 mm; ZZZ_V M_c01_Y_Length: -102.5 mm
Phasing - Phase Created: New Construction
Text - RSen_C_content_manual: https://thorbiq.freshdesk.com/support/solutions

# IfcEnergyConversionDevice: cyqs200dk100rbn - small - white_daikin_lxwxh 2048x308x101,5 mm, RSen_57_AIR_FB_air curtain - suction grid - 10 connections_daikin:cyqs200dk100rbn - small - white_daikin_lxwxh 2048x308x101,5 mm:1285484
In: Level 1
Type - PredefinedType: AIRHANDLER; Classification: 57.10.10.20 (Uniformat)
Type - Constraints - Default Elevation: 0 mm
Type - Construction - TBQen_C_diameter_type_index: 1; TBQen_C_diameter_type: OD; TBQen_C_SOg_AIR_01: RSen_57_AIR_FB_SOg - cyqs200dk100rbn - SH_daikin_tbq: standard; TBQen_C_SOg_AIR_02: standard
Type - Dimensions - RSen_C_height: 102 mm; RSen_C_length: 2048 mm; RSen_C_width: 308 mm
Type - Identity Data - Assembly Code: 57.10.10.20; Description: Heat Pump; Manufacturer: Daikin Europe N.V.; Model: Air Curtain; OmniClass Number: 23.75.35.17.21; OmniClass Title: Air Curtains; RSen_C_code_article: CYQS200DK100RBN; RSen_C_code_ETIM: Air curtain for cold application; RSen_C_code_ETIM_URL: https://prod.etim-international.com/Class/Details?classId=EC011450&classVersion=4; RSen_C_code_gtin: -; RSen_C_code_product_class: CYQS-DK-R; RSen_C_content_creator: © ThorbiQ; RSen_C_content_date_changed: 14/01/2021; RSen_C_content_date_issue: 14/01/2021; RSen_C_content_provider: Daikin Europe N.V.; RSen_C_content_version: 2.0.0; RSen_C_description: Heat Pump; RSen_C_description_01: Small - white; RSen_C_model: Air Curtain; RSen_C_revit_version: 2018; RSen_C_type: Air Curtain, Concealed Ceiling; RSen_C_type_comments: Air Curtain; TBQ_I BaseKeynote: 57.10.10.20; TBQen_C_code_product: CYQS200DK100RBN; TBQen_C_IFC_version: 2x3; TBQen_C_license: Creative Commons Attribution NoDerivs (CC-ND); TBQen_C_license_info: https://tldrlegal.com/license/creative-commons-attribution-noderivs-(cc-nd)#summary; Type Comments: Air Curtain; Type Name: cyqs200dk100rbn - small - white_daikin_lxwxh 2048x308x101,5 mm; URL: www.daikineurope.com
Type - Materials and Finishes - RSen_C_material: RSen_x_rgb 255 255 255 T00 pure white_gen
Type - Model Properties - TBQen_C_mounting_ceiling: yes; TBQen_C_mounting_floor: no; TBQen_C_mounting_wall: no
Type - Other - Category: Air Terminals; Family Name: RSen_57_AIR_FB_air curtain - suction grid - 10 connections_daikin; RSen_M_c01_description: c01_fitting; RSen_M_c01_diameter: 160 mm; RSen_M_c01_height: 0 mm; RSen_M_c01_width: 0 mm; RSen_M_c02_description: c02_fitting; RSen_M_c02_diameter: 160 mm; RSen_M_c02_height: 0 mm; RSen_M_c02_width: 0 mm; RSen_M_c03_description: c03_fitting; RSen_M_c03_diameter: 160 mm; RSen_M_c03_height: 0 mm; RSen_M_c03_width: 0 mm; RSen_M_c04_description: c04_fitting; RSen_M_c04_diameter: 160 mm; RSen_M_c04_height: 0 mm; RSen_M_c04_width: 0 mm; RSen_M_c05_description: c05_fitting; RSen_M_c05_diameter: 160 mm; RSen_M_c05_height: 0 mm; RSen_M_c05_width: 0 mm; RSen_M_c06_description: c06_fitting; RSen_M_c06_diameter: 160 mm; RSen_M_c06_height: 0 mm; RSen_M_c06_width: 0 mm; RSen_M_c07_description: c07_fitting; RSen_M_c07_diameter: 160 mm; RSen_M_c07_height: 0 mm; RSen_M_c07_width: 0 mm; RSen_M_c08_description: c08_fitting; RSen_M_c08_diameter: 160 mm; RSen_M_c08_height: 0 mm; RSen_M_c08_width: 0 mm; RSen_M_c09_description: c09_fitting; RSen_M_c09_diameter: 160 mm; RSen_M_c09_height: 0 mm; RSen_M_c09_width: 0 mm; RSen_M_c10_description: c10_fitting; RSen_M_c10_diameter: 160 mm; RSen_M_c10_height: 0 mm; RSen_M_c10_width: 0 mm; TBQen_M_c01_flow_configuration: -; TBQen_M_c01_flow_direction: Out; TBQen_M_c01_loss_method: Not Defined; TBQen_M_c01_shape: Round; TBQen_M_c01_system_classification: Fitting; TBQen_M_c01_yes_no: yes; TBQen_M_c02_flow_configuration: -; TBQen_M_c02_flow_direction: Out; TBQen_M_c02_loss_method: Not Defined; TBQen_M_c02_shape: Round; TBQen_M_c02_system_classification: Fitting; TBQen_M_c02_yes_no: yes; TBQen_M_c03_flow_configuration: -; TBQen_M_c03_flow_direction: Out; TBQen_M_c03_loss_method: Not Defined; TBQen_M_c03_shape: Round; TBQen_M_c03_system_classification: Fitting; TBQen_M_c03_yes_no: yes; TBQen_M_c04_flow_configuration: -; TBQen_M_c04_flow_direction: Out; TBQen_M_c04_loss_method: Not Defined; TBQen_M_c04_shape: Round; TBQen_M_c04_system_classification: Fitting; TBQen_M_c04_yes_no: yes; TBQen_M_c05_flow_configuration: -; TBQen_M_c05_flow_direction: Out; TBQen_M_c05_loss_method: Not Defined; TBQen_M_c05_shape: Round; TBQen_M_c05_system_classification: Fitting; TBQen_M_c05_yes_no: yes; TBQen_M_c06_flow_configuration: -; TBQen_M_c06_flow_direction: Out; TBQen_M_c06_loss_method: Not Defined; TBQen_M_c06_shape: Round; TBQen_M_c06_system_classification: Fitting; TBQen_M_c06_yes_no: yes; TBQen_M_c07_flow_configuration: -; TBQen_M_c07_flow_direction: Out; TBQen_M_c07_loss_method: Not Defined; TBQen_M_c07_shape: Round; TBQen_M_c07_system_classification: Fitting; TBQen_M_c07_yes_no: yes; TBQen_M_c08_flow_configuration: -; TBQen_M_c08_flow_direction: Out; TBQen_M_c08_loss_method: Not Defined; TBQen_M_c08_shape: Round; TBQen_M_c08_system_classification: Fitting; TBQen_M_c08_yes_no: yes; TBQen_M_c09_flow_configuration: -; TBQen_M_c09_flow_direction: Out; TBQen_M_c09_loss_method: Not Defined; TBQen_M_c09_shape: Round; TBQen_M_c09_system_classification: Fitting; TBQen_M_c09_yes_no: yes; TBQen_M_c10_flow_configuration: -; TBQen_M_c10_flow_direction: Out; TBQen_M_c10_loss_method: Not Defined; TBQen_M_c10_shape: Round; TBQen_M_c10_system_classification: Fitting; TBQen_M_c10_yes_no: yes
Pset_ManufacturerTypeInformation - Manufacturer: Daikin Europe N.V.
Pset_DistributionFlowElementCommon - Reference: cyqs200dk100rbn - small - white_daikin_lxwxh 2048x308x101,5 mm
Constraints - Level: Level: Level 1; Elevation: 2500 mm; Host: Reference Plane : ceiling
Construction - TBQen_C_alignment_index: 0; TBQen_C_GOg: no; TBQen_C_SOg: yes; TBQen_C_alignment: Center; TBQen_C_suspension_height: 150 mm
Dimensions - Area: 23.0318 m2; Size: 160 mmø-160 mmø-160 mmø-160 mmø-160 mmø-160 mmø-160 mmø-160 mmø-160 mmø-160 mmø; Volume: 1.63391 m3
Graphics - TBQen_C_clearance_zone: no; TBQen_C_connection_zone: no; TBQen_C_maintenance_zone: no; TBQen_C_neighbour_unit: no; TBQen_C_neighbour_unit_displacement_back: 0 mm; TBQen_C_neighbour_unit_displacement_front: 0 mm; TBQen_C_neighbour_unit_displacement_left: 0 mm; TBQen_C_neighbour_unit_displacement_right: 0 mm; TBQen_C_logo: yes
Identity Data - Mark: 3
Mechanical - System Classification: Undefined
Mechanical - Flow - Flow: 0 m3/s
Other - Schedule Level: Level: Level 1; Family: RSen_57_AIR_FB_air curtain - suction grid - 10 connections_daikin: cyqs200dk100rbn - small - white_daikin_lxwxh 2048x308x101,5 mm; Family and Type: RSen_57_AIR_FB_air curtain - suction grid - 10 connections_daikin: cyqs200dk100rbn - small - white_daikin_lxwxh 2048x308x101,5 mm; Type: RSen_57_AIR_FB_air curtain - suction grid - 10 connections_daikin: cyqs200dk100rbn - small - white_daikin_lxwxh 2048x308x101,5 mm; Type Id: RSen_57_AIR_FB_air curtain - suction grid - 10 connections_daikin: cyqs200dk100rbn - small - white_daikin_lxwxh 2048x308x101,5 mm; ZZZ_V M_c01_plane_Integer: 2; ZZZ_V M_c01_X_Length: 900 mm; ZZZ_V M_c01_Y_Length: 0 mm
Phasing - Phase Created: New Construction
Text - RSen_C_content_manual: https://thorbiq.freshdesk.com/support/solutions

# IfcEnergyConversionDevice: cyvl250dk250csc - large - grey_daikin_lxwxh 2500x1105x370 mm, RSen_57_ME_FB_air curtain_daikin:cyvl250dk250csc - large - grey_daikin_lxwxh 2500x1105x370 mm:1185804
In: Level 1
Type - PredefinedType: AIRHANDLER; Classification: 57.10.10.20 (Uniformat); Material: RSen_x_rgb 188 188 190 T00 gray_gen
Type - Constraints - Default Elevation: 0 mm
Type - Construction - TBQen_C_diameter_type: OD; TBQen_C_diameter_type_index: 1; TBQen_C_SOg_ME_01: RSen_57_ME_FB_SOg - cyvl250dk250csc - SH_daikin_tbq: standard; TBQen_C_SOg_ME_02: standard
Type - Dimensions - RSen_C_height: 370 mm; RSen_C_length: 2500 mm; RSen_C_width: 1105 mm
Type - Electrical - RSen_E_c01_apparent_power: 1880 W; RSen_E_c01_current: 0 A; RSen_E_c01_division_engine: no; RSen_E_c01_load_class: Other; RSen_E_c01_number_of_poles: 1; RSen_E_c01_voltage: 230 V; TBQen_E_c01_power: 1880 W; TBQen_E_c01_power_factor: 1
Type - Identity Data - Assembly Code: 57.10.10.20; Description: Heat Pump; Manufacturer: Daikin Europe N.V.; Model: Air Curtain; OmniClass Number: 23.75.35.17.21; OmniClass Title: Air Curtains; RSen_C_code_article: CYVL250DK250CSC; RSen_C_code_ETIM: Air curtain for cold application; RSen_C_code_ETIM_URL: https://prod.etim-international.com/Class/Details?classId=EC011450&classVersion=4; RSen_C_code_gtin: -; RSen_C_code_product_class: CYVL-DK-C; RSen_C_content_creator: © ThorbiQ; RSen_C_content_date_changed: 14/01/2021; RSen_C_content_date_issue: 14/01/2021; RSen_C_content_provider: Daikin Europe N.V.; RSen_C_content_version: 2.0.0; RSen_C_description: Heat Pump; RSen_C_description_01: Large - grey; RSen_C_description_02: Cassette; RSen_C_model: Air Curtain; RSen_C_revit_version: 2018; RSen_C_type: Air curtain, cassette; RSen_C_type_comments: Air Curtain; TBQ_I BaseKeynote: 57.10.10.20; TBQen_C_code_product: CYVL250DK250CSC; TBQen_C_IFC_version: 2x3; TBQen_C_license: Creative Commons Attribution NoDerivs (CC-ND); TBQen_C_license_info: https://tldrlegal.com/license/creative-commons-attribution-noderivs-(cc-nd)#summary; Type Comments: Air Curtain; Type Name: cyvl250dk250csc - large - grey_daikin_lxwxh 2500x1105x370 mm; URL: www.daikineurope.com
Type - Materials and Finishes - RSen_C_material: RSen_x_rgb 188 188 190 T00 gray_gen
Type - Mechanical - RSen_P_c01_volume_flow: 0 m3/s; RSen_P_c02_volume_flow: 0 m3/s; TBQ_I Air flow rate_speed 1: 0.0390227 m3/s; TBQ_I Air flow rate_speed 2: 0.0504215 m3/s; TBQ_I Air flow rate_speed 3: 0.0760246 m3/s
Type - Model Properties - TBQen_C_mounting_ceiling: yes; TBQen_C_mounting_floor: no; TBQen_C_mounting_wall: no
Type - Other - Category: Mechanical Equipment; Family Name: RSen_57_ME_FB_air curtain_daikin; RSen_E_c01_description: c01_el; RSen_E_c02_description: c02_controls; RSen_P_c01_description: c01_liquid piping connection; RSen_P_c01_diameter: 9.52 mm; RSen_P_c02_description: c02_gas piping connection; RSen_P_c02_diameter: 22 mm; TBQen_E_c01_power_factor_state: Lagging; TBQen_E_c01_system_type: Power - Balanced; TBQen_E_c01_yes_no: yes; TBQen_E_c02_yes_no: yes; TBQen_P_c01_diameter_calc: 9.5 mm; TBQen_P_c01_flow_configuration: Preset; TBQen_P_c01_flow_direction: In; TBQen_P_c01_loss_method: Not Defined; TBQen_P_c01_system_classification: Hydronic Supply; TBQen_P_c01_yes_no: yes; TBQen_P_c02_diameter_calc: 22 mm; TBQen_P_c02_flow_configuration: Preset; TBQen_P_c02_flow_direction: Out; TBQen_P_c02_loss_method: Not Defined; TBQen_P_c02_system_classification: Hydronic Return; TBQen_P_c02_yes_no: yes
Pset_ManufacturerTypeInformation - Manufacturer: Daikin Europe N.V.
Pset_DistributionFlowElementCommon - Reference: cyvl250dk250csc - large - grey_daikin_lxwxh 2500x1105x370 mm
Constraints - Level: Level: Level 1; Elevation: 2500 mm; Host: Reference Plane : ceiling
Construction - TBQen_C_alignment: Center; TBQen_C_alignment_index: 0; TBQen_C_GOg: no; TBQen_C_SOg: yes; TBQen_C_suspension_height: 150 mm
Dimensions - Area: 70.5572 m2; Volume: 17.3789 m3
Graphics - TBQen_C_clearance_zone: no; TBQen_C_connection_zone: no; TBQen_C_logo: no; TBQen_C_maintenance_zone: no; TBQen_C_neighbour_unit: no; TBQen_C_neighbour_unit_displacement_back: 0 mm; TBQen_C_neighbour_unit_displacement_front: 0 mm; TBQen_C_neighbour_unit_displacement_left: 0 mm; TBQen_C_neighbour_unit_displacement_right: 0 mm
Identity Data - Mark: 57
Mechanical - System Classification: Hydronic Return,Hydronic Supply,Power,Controls
Mechanical - Flow - TBQen_M_flow_rate: 0.0760246 m3/s; TBQen_M_flow_rate_index: 2; TBQen_M_flow_rate_info: Speed 3
Other - Schedule Level: Level: Level 1; Family: RSen_57_ME_FB_air curtain_daikin: cyvl250dk250csc - large - grey_daikin_lxwxh 2500x1105x370 mm; Family and Type: RSen_57_ME_FB_air curtain_daikin: cyvl250dk250csc - large - grey_daikin_lxwxh 2500x1105x370 mm; Type: RSen_57_ME_FB_air curtain_daikin: cyvl250dk250csc - large - grey_daikin_lxwxh 2500x1105x370 mm; Type Id: RSen_57_ME_FB_air curtain_daikin: cyvl250dk250csc - large - grey_daikin_lxwxh 2500x1105x370 mm
Phasing - Phase Created: New Construction
Text - RSen_C_content_manual: https://thorbiq.freshdesk.com/support/solutions

# IfcEnergyConversionDevice: cyvl250dk250fsc - large - grey_daikin_lxwxh 2500x774x370 mm, RSen_57_ME_FB_air curtain_daikin:cyvl250dk250fsc - large - grey_daikin_lxwxh 2500x774x370 mm:1185805
In: Level 1
Type - PredefinedType: AIRHANDLER; Classification: 57.10.10.20 (Uniformat); Material: RSen_x_rgb 188 188 190 T00 gray_gen
Type - Constraints - Default Elevation: 0 mm
Type - Construction - TBQen_C_diameter_type_index: 1; TBQen_C_SOg_ME_02: standard; TBQen_C_diameter_type: OD; TBQen_C_SOg_ME_01: RSen_57_ME_FB_SOg - cyvl250dk250fsc - SH_daikin_tbq: standard
Type - Dimensions - RSen_C_height: 370 mm; RSen_C_length: 2500 mm; RSen_C_width: 774 mm
Type - Electrical - RSen_E_c01_division_engine: no; RSen_E_c01_load_class: Other; RSen_E_c01_number_of_poles: 1; TBQen_E_c01_power_factor: 1; RSen_E_c01_apparent_power: 1880 W; RSen_E_c01_current: 0 A; RSen_E_c01_voltage: 230 V; TBQen_E_c01_power: 1880 W
Type - Identity Data - Assembly Code: 57.10.10.20; Description: Heat Pump; Manufacturer: Daikin Europe N.V.; Model: Air Curtain; OmniClass Number: 23.75.35.17.21; OmniClass Title: Air Curtains; RSen_C_code_article: CYVL250DK250FSC; RSen_C_code_ETIM: Air curtain for cold application; RSen_C_code_ETIM_URL: https://prod.etim-international.com/Class/Details?classId=EC011450&classVersion=4; RSen_C_code_gtin: -; RSen_C_code_product_class: CYVL-DK-F; RSen_C_content_creator: © ThorbiQ; RSen_C_content_date_changed: 14/01/2021; RSen_C_content_date_issue: 14/01/2021; RSen_C_content_provider: Daikin Europe N.V.; RSen_C_content_version: 2.0.0; RSen_C_description: Heat Pump; RSen_C_description_01: Large - grey; RSen_C_description_02: Free hanging; RSen_C_model: Air Curtain; RSen_C_revit_version: 2018; RSen_C_type: Air curtain, wall mounted; RSen_C_type_comments: Air Curtain; TBQ_I BaseKeynote: 57.10.10.20; TBQen_C_code_product: CYVL250DK250FSC; TBQen_C_IFC_version: 2x3; TBQen_C_license: Creative Commons Attribution NoDerivs (CC-ND); TBQen_C_license_info: https://tldrlegal.com/license/creative-commons-attribution-noderivs-(cc-nd)#summary; Type Comments: Air Curtain; Type Name: cyvl250dk250fsc - large - grey_daikin_lxwxh 2500x774x370 mm; URL: www.daikineurope.com
Type - Materials and Finishes - RSen_C_material: RSen_x_rgb 188 188 190 T00 gray_gen
Type - Mechanical - RSen_P_c01_volume_flow: 0 m3/s; RSen_P_c02_volume_flow: 0 m3/s; TBQ_I Air flow rate_speed 1: 0.0390227 m3/s; TBQ_I Air flow rate_speed 2: 0.0504215 m3/s; TBQ_I Air flow rate_speed 3: 0.0760246 m3/s
Type - Model Properties - TBQen_C_mounting_ceiling: yes; TBQen_C_mounting_floor: no; TBQen_C_mounting_wall: no
Type - Other - Category: Mechanical Equipment; TBQen_E_c01_yes_no: yes; TBQen_E_c02_yes_no: yes; TBQen_P_c01_yes_no: yes; TBQen_P_c02_yes_no: yes; Family Name: RSen_57_ME_FB_air curtain_daikin; RSen_E_c01_description: c01_el; RSen_E_c02_description: c02_controls; RSen_P_c01_description: c01_liquid piping connection; RSen_P_c01_diameter: 9.52 mm; RSen_P_c02_description: c02_gas piping connection; RSen_P_c02_diameter: 22 mm; TBQen_E_c01_power_factor_state: Lagging; TBQen_E_c01_system_type: Power - Balanced; TBQen_P_c01_diameter_calc: 9.5 mm; TBQen_P_c01_flow_configuration: Preset; TBQen_P_c01_flow_direction: In; TBQen_P_c01_loss_method: Not Defined; TBQen_P_c01_system_classification: Hydronic Supply; TBQen_P_c02_diameter_calc: 22 mm; TBQen_P_c02_flow_configuration: Preset; TBQen_P_c02_flow_direction: Out; TBQen_P_c02_loss_method: Not Defined; TBQen_P_c02_system_classification: Hydronic Return
Pset_ManufacturerTypeInformation - Manufacturer: Daikin Europe N.V.
Pset_DistributionFlowElementCommon - Reference: cyvl250dk250fsc - large - grey_daikin_lxwxh 2500x774x370 mm
Constraints - Level: Level: Level 1; Elevation: 2500 mm; Host: Reference Plane : ceiling
Construction - TBQen_C_alignment_index: 0; TBQen_C_GOg: no; TBQen_C_SOg: yes; TBQen_C_alignment: Center; TBQen_C_suspension_height: 150 mm
Dimensions - Area: 54.4328 m2; Volume: 12.174 m3
Graphics - TBQen_C_clearance_zone: no; TBQen_C_connection_zone: no; TBQen_C_logo: no; TBQen_C_maintenance_zone: no; TBQen_C_neighbour_unit: no; TBQen_C_neighbour_unit_displacement_back: 0 mm; TBQen_C_neighbour_unit_displacement_front: 0 mm; TBQen_C_neighbour_unit_displacement_left: 0 mm; TBQen_C_neighbour_unit_displacement_right: 0 mm
Identity Data - Mark: 58
Mechanical - System Classification: Hydronic Return,Hydronic Supply,Power,Controls
Mechanical - Flow - TBQen_M_flow_rate_index: 2; TBQen_M_flow_rate: 0.0760246 m3/s; TBQen_M_flow_rate_info: Speed 3
Other - Schedule Level: Level: Level 1; Family: RSen_57_ME_FB_air curtain_daikin: cyvl250dk250fsc - large - grey_daikin_lxwxh 2500x774x370 mm; Family and Type: RSen_57_ME_FB_air curtain_daikin: cyvl250dk250fsc - large - grey_daikin_lxwxh 2500x774x370 mm; Type: RSen_57_ME_FB_air curtain_daikin: cyvl250dk250fsc - large - grey_daikin_lxwxh 2500x774x370 mm; Type Id: RSen_57_ME_FB_air curtain_daikin: cyvl250dk250fsc - large - grey_daikin_lxwxh 2500x774x370 mm
Phasing - Phase Created: New Construction
Text - RSen_C_content_manual: https://thorbiq.freshdesk.com/support/solutions

# IfcEnergyConversionDevice: fcahg71gveb - high cop round flow cassette - auto-cleaning panel_daikin_lxwxh 950x950x418 mm, RSen_55_ME_FB_indoor unit - sky air - cassette-wall-floor_daikin:fcahg71gveb - high cop round flow cassette - auto-cleaning panel_daikin_lxwxh 950x950x418 mm:2162874
In: Level 1
Type - PredefinedType: AIRCONDITIONINGUNIT; Material: RSen_x_rgb 255 255 255 T00 pure white_gen
Type - Constraints - Default Elevation: 0 mm
Type - Construction - TBQen_C_diameter_type_index: 1; TBQen_C_SOg_ME_02: standard; TBQen_C_accessory_01_index: 0; TBQen_C_diameter_type: OD; TBQen_C_SOg_ME_01: RSen_55_ME_FB_SOg - fcahg71gveb - auto-cleaning panel - SH_daikin_tbq: standard
Type - Dimensions - RSen_C_height: 418 mm; RSen_C_length: 950 mm; RSen_C_width: 950 mm
Type - Electrical - RSen_E_c01_division_engine: no; RSen_E_c01_load_class: Other; RSen_E_c01_number_of_poles: 1; TBQen_E_c01_power_factor: 1; RSen_E_c01_apparent_power: 0 W; RSen_E_c01_current: 0 A; RSen_E_c01_voltage: 230 V; TBQen_E_c01_power: 0 W
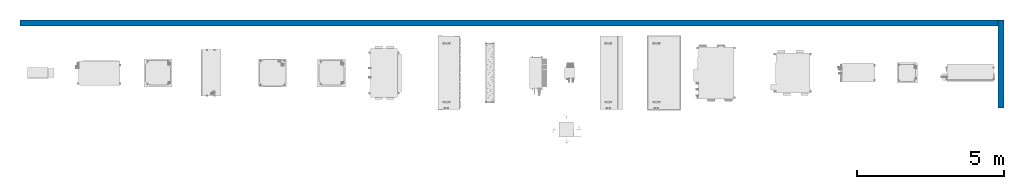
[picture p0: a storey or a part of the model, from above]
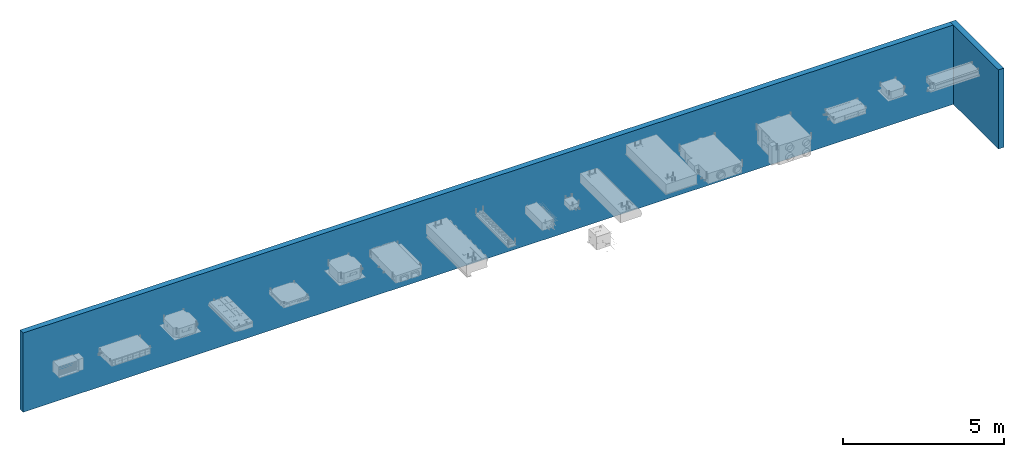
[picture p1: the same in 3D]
Properties of the parts of a building model (IFC2X3), part 2 of 3

# IfcEnergyConversionDevice: fcahg71gveb - high cop round flow cassette - auto-cleaning panel_daikin_lxwxh 950x950x418 mm, RSen_55_ME_FB_indoor unit - sky air - cassette-wall-floor_daikin:fcahg71gveb - high cop round flow cassette - auto-cleaning panel_daikin_lxwxh 950x950x418 mm:2162874
Type - Identity Data - Description: Ceiling mounted cassette; Manufacturer: Daikin Europe N.V.; Model: Sky Air; OmniClass Number: 23.75.10.24.21.27.24; OmniClass Title: Room Air Conditioners; RSen_C_code_article: FCAHG71GVEB; RSen_C_code_ETIM: Air-conditioning split system – inside unit (evaporator); RSen_C_code_ETIM_URL: https://prod.etim-international.com/Class/Details?classId=EC011580&classVersion=4; RSen_C_code_gtin: -; RSen_C_code_product_class: FCAHG-G; RSen_C_content_creator: © ThorbiQ; RSen_C_content_date_changed: 14/01/2021; RSen_C_content_date_issue: 14/01/2021; RSen_C_content_provider: Daikin Europe N.V.; RSen_C_content_version: 2.0.0; RSen_C_description: Ceiling mounted cassette; RSen_C_model: Sky Air; RSen_C_revit_version: 2018; RSen_C_type: High COP round flow cassette; RSen_C_type_comments: Indoor unit; TBQ_I BaseKeynote: 55.10.10.10; TBQen_C_code_product: FCAHG71G; TBQen_C_IFC_version: 2x3; TBQen_C_license: Creative Commons Attribution NoDerivs (CC-ND); TBQen_C_license_info: https://tldrlegal.com/license/creative-commons-attribution-noderivs-(cc-nd)#summary; Type Comments: Indoor unit; Type Name: fcahg71gveb - high cop round flow cassette - auto-cleaning panel_daikin_lxwxh 950x950x418 mm; URL: www.daikineurope.com
Type - Materials and Finishes - RSen_C_material: RSen_x_rgb 255 255 255 T00 pure white_gen
Type - Mechanical - RSen_P_c03_load_value: 0; TBQ_I Fresh air_percentage intake: 10; RSen_P_c01_volume_flow: 0 m3/s; RSen_P_c02_volume_flow: 0 m3/s; TBQ_I Air flow rate_speed 1: 7.18065 m3/s; TBQ_I Air flow rate_speed 2: 9.82925 m3/s; TBQ_I Air flow rate_speed 3: 12.4778 m3/s
Type - Model Properties - TBQen_C_mounting_ceiling: yes; TBQen_C_mounting_floor: no; TBQen_C_mounting_wall: no
Type - Other - Category: Mechanical Equipment; TBQen_E_c01_yes_no: yes; TBQen_E_c02_yes_no: yes; TBQen_P_c01_yes_no: yes; TBQen_P_c02_yes_no: yes; TBQen_P_c03_yes_no: yes; Family Name: RSen_55_ME_FB_indoor unit - sky air - cassette-wall-floor_daikin; RSen_E_c01_description: c01_el; RSen_E_c02_description: c02_controls; RSen_P_c01_description: c02_liquid piping connection; RSen_P_c01_diameter: 9.52 mm; RSen_P_c02_description: c03_gas piping connection; RSen_P_c02_diameter: 15.9 mm; RSen_P_c03_description: c04_drain piping connection; RSen_P_c03_diameter: 32 mm; TBQen_E_c01_power_factor_state: Lagging; TBQen_E_c01_system_type: Power - Balanced; TBQen_P_c01_diameter_calc: 9.5 mm; TBQen_P_c01_flow_configuration: Preset; TBQen_P_c01_flow_direction: In; TBQen_P_c01_loss_method: Not Defined; TBQen_P_c01_system_classification: Hydronic Supply; TBQen_P_c02_diameter_calc: 15.9 mm; TBQen_P_c02_flow_configuration: Preset; TBQen_P_c02_flow_direction: Out; TBQen_P_c02_loss_method: Not Defined; TBQen_P_c02_system_classification: Hydronic Return; TBQen_P_c03_diameter_calc: 32 mm; TBQen_P_c03_flow_configuration: Fixture Units; TBQen_P_c03_flow_direction: Out; TBQen_P_c03_loss_method: Not Defined; TBQen_P_c03_system_classification: Sanitary
Pset_ManufacturerTypeInformation - Manufacturer: Daikin Europe N.V.
Pset_DistributionFlowElementCommon - Reference: fcahg71gveb - high cop round flow cassette - auto-cleaning panel_daikin_lxwxh 950x950x418 mm
Constraints - Level: Level: Level 1; Elevation: 2500 mm; Host: Reference Plane : ceiling
Construction - TBQen_C_alignment_index: 0; TBQen_C_GOg: no; TBQen_C_SOg: yes; TBQen_C_alignment: Center; TBQen_C_suspension_height: 20 mm
Dimensions - Area: 71.5284 m2; Volume: 52.6214 m3
Graphics - TBQen_C_clearance_zone: no; TBQen_C_connection_zone: no; TBQen_C_logo: no; TBQen_C_maintenance_zone: no; TBQen_C_neighbour_unit: no; TBQen_C_neighbour_unit_displacement_back: 0 mm; TBQen_C_neighbour_unit_displacement_front: 0 mm; TBQen_C_neighbour_unit_displacement_left: 0 mm; TBQen_C_neighbour_unit_displacement_right: 0 mm
Identity Data - Mark: 129
Mechanical - System Classification: Hydronic Return,Hydronic Supply,Sanitary,Power,Controls
Mechanical - Flow - TBQen_M_flow_rate_index: 1; TBQen_M_flow_rate: 9.82925 m3/s; TBQen_M_flow_rate_info: Norm.
Other - Schedule Level: Level: Level 1; ZZZ_V P_c01_plane_Integer: 3; Family: RSen_55_ME_FB_indoor unit - sky air - cassette-wall-floor_daikin: fcahg71gveb - high cop round flow cassette - auto-cleaning panel_daikin_lxwxh 950x950x418 mm; Family and Type: RSen_55_ME_FB_indoor unit - sky air - cassette-wall-floor_daikin: fcahg71gveb - high cop round flow cassette - auto-cleaning panel_daikin_lxwxh 950x950x418 mm; Type: RSen_55_ME_FB_indoor unit - sky air - cassette-wall-floor_daikin: fcahg71gveb - high cop round flow cassette - auto-cleaning panel_daikin_lxwxh 950x950x418 mm; Type Id: RSen_55_ME_FB_indoor unit - sky air - cassette-wall-floor_daikin: fcahg71gveb - high cop round flow cassette - auto-cleaning panel_daikin_lxwxh 950x950x418 mm; ZZZ_V P_c01_X_Length: -280 mm; ZZZ_V P_c01_Y_Length: -21 mm
Phasing - Phase Created: New Construction
Text - RSen_C_content_manual: https://thorbiq.freshdesk.com/support/solutions

# IfcEnergyConversionDevice: fdxm60f3v1b9 - slim concealed ceiling unit_daikin_lxwxh 620x1150x200 mm, RSen_55_ME_FB_indoor unit - sky air - concealed ceiling-floor_daikin:fdxm60f3v1b9 - slim concealed ceiling unit_daikin_lxwxh 620x1150x200 mm:2332156
In: Level 1
Type - PredefinedType: AIRCONDITIONINGUNIT; Material: RSen_x_rgb 255 255 255 T00 pure white_gen
Type - Constraints - Default Elevation: 0 mm
Type - Construction - TBQen_C_diameter_type_index: 1; TBQen_C_SOg_ME_02: standard; TBQen_C_accessory_01_index: 0; TBQen_C_diameter_type: OD; TBQen_C_SOg_ME_01: RSen_55_ME_FB_SOg - fdxm60f3v1b9 - SH_daikin_tbq: standard
Type - Dimensions - RSen_C_height: 200 mm; RSen_C_length: 620 mm; RSen_C_width: 1150 mm
Type - Electrical - RSen_E_c01_division_engine: no; RSen_E_c01_load_class: Other; RSen_E_c01_number_of_poles: 1; TBQen_E_c01_power_factor: 1; RSen_E_c01_apparent_power: 0 W; RSen_E_c01_current: 0 A; RSen_E_c01_voltage: 230 V; TBQen_E_c01_power: 0 W
Type - Identity Data - Description: Concealed ceiling; Manufacturer: Daikin Europe N.V.; Model: Sky Air; OmniClass Number: 23.75.10.24.21.27.24; OmniClass Title: Room Air Conditioners; RSen_C_code_article: FDXM60F3V1B9; RSen_C_code_ETIM: Air-conditioning split system – inside unit (evaporator); RSen_C_code_ETIM_URL: https://prod.etim-international.com/Class/Details?classId=EC011580&classVersion=4; RSen_C_code_gtin: -; RSen_C_code_product_class: FDXM-F9; RSen_C_content_creator: © ThorbiQ; RSen_C_content_date_changed: 14/01/2021; RSen_C_content_date_issue: 14/01/2021; RSen_C_content_provider: Daikin Europe N.V.; RSen_C_content_version: 2.0.0; RSen_C_description: Concealed ceiling; RSen_C_model: Sky Air; RSen_C_revit_version: 2018; RSen_C_type: Slim concealed ceiling unit; RSen_C_type_comments: Indoor unit; TBQ_I BaseKeynote: 55.10.10.10; TBQen_C_code_product: FDXM60F9; TBQen_C_IFC_version: 2x3; TBQen_C_license: Creative Commons Attribution NoDerivs (CC-ND); TBQen_C_license_info: https://tldrlegal.com/license/creative-commons-attribution-noderivs-(cc-nd)#summary; Type Comments: Indoor unit; Type Name: fdxm60f3v1b9 - slim concealed ceiling unit_daikin_lxwxh 620x1150x200 mm; URL: www.daikineurope.com
Type - Materials and Finishes - RSen_C_material: RSen_x_rgb 255 255 255 T00 pure white_gen
Type - Mechanical - RSen_P_c03_load_value: 0; TBQ_I Fresh air_percentage intake: 0; RSen_P_c01_volume_flow: 0 m3/s; RSen_P_c02_volume_flow: 0 m3/s; TBQ_I Air flow rate_speed 1: 7.9458 m3/s; TBQ_I Air flow rate_speed 2: 8.71095 m3/s; TBQ_I Air flow rate_speed 3: 9.41724 m3/s
Type - Model Properties - TBQen_C_mounting_ceiling: yes; TBQen_C_mounting_floor: no; TBQen_C_mounting_wall: no
Type - Other - Category: Mechanical Equipment; TBQen_E_c01_yes_no: yes; TBQen_E_c02_yes_no: yes; TBQen_P_c01_yes_no: yes; TBQen_P_c02_yes_no: yes; TBQen_P_c03_yes_no: yes; TBQen_M_c01_yes_no: yes; TBQen_M_c02_yes_no: yes; RSen_M_c01_diameter: 0 mm; RSen_M_c02_diameter: 0 mm; TBQen_M_c01_optional: no; TBQen_M_c02_optional: no; Family Name: RSen_55_ME_FB_indoor unit - sky air - concealed ceiling-floor_daikin; RSen_E_c01_description: c01_el; RSen_E_c02_description: c02_controls; RSen_M_c01_description: c05_return air; RSen_M_c01_height: 160 mm; RSen_M_c01_width: 980 mm; RSen_M_c02_description: c06_supply air; RSen_M_c02_height: 153 mm; RSen_M_c02_width: 1060 mm; RSen_P_c01_description: c02_liquid piping connection; RSen_P_c01_diameter: 6.35 mm; RSen_P_c02_description: c03_gas piping connection; RSen_P_c02_diameter: 12.7 mm; RSen_P_c03_description: c04_drain piping connection; RSen_P_c03_diameter: 26 mm; TBQen_E_c01_power_factor_state: Lagging; TBQen_E_c01_system_type: Power - Balanced; TBQen_M_c01_flow_configuration: Preset; TBQen_M_c01_flow_direction: in; TBQen_M_c01_loss_method: Not Defined; TBQen_M_c01_shape: Rectangular; TBQen_M_c01_system_classification: Return Air; TBQen_M_c02_flow_configuration: Preset; TBQen_M_c02_flow_direction: Out; TBQen_M_c02_loss_method: Not Defined; TBQen_M_c02_shape: Rectangular; TBQen_M_c02_system_classification: Supply Air; TBQen_P_c01_diameter_calc: 6.4 mm; TBQen_P_c01_flow_configuration: Preset; TBQen_P_c01_flow_direction: In; TBQen_P_c01_loss_method: Not Defined; TBQen_P_c01_system_classification: Hydronic Supply; TBQen_P_c02_diameter_calc: 12.7 mm; TBQen_P_c02_flow_configuration: Preset; TBQen_P_c02_flow_direction: Out; TBQen_P_c02_loss_method: Not Defined; TBQen_P_c02_system_classification: Hydronic Return; TBQen_P_c03_diameter_calc: 26 mm; TBQen_P_c03_flow_configuration: Fixture Units; TBQen_P_c03_flow_direction: Out; TBQen_P_c03_loss_method: Not Defined; TBQen_P_c03_system_classification: Sanitary
Pset_ManufacturerTypeInformation - Manufacturer: Daikin Europe N.V.
Pset_DistributionFlowElementCommon - Reference: fdxm60f3v1b9 - slim concealed ceiling unit_daikin_lxwxh 620x1150x200 mm
Constraints - Level: Level: Level 1; Elevation: 2500 mm; Host: Reference Plane : ceiling
Construction - TBQen_C_alignment_index: 0; TBQen_C_GOg: no; TBQen_C_SOg: yes; TBQen_C_alignment: Center; TBQen_C_suspension_height: 20 mm
Dimensions - Area: 24.5502 m2; Volume: 3.22319 m3
Graphics - TBQen_C_clearance_zone: no; TBQen_C_connection_zone: no; TBQen_C_logo: no; TBQen_C_maintenance_zone: no; TBQen_C_neighbour_unit: no; TBQen_C_neighbour_unit_displacement_back: 0 mm; TBQen_C_neighbour_unit_displacement_front: 0 mm; TBQen_C_neighbour_unit_displacement_left: 0 mm; TBQen_C_neighbour_unit_displacement_right: 0 mm
Identity Data - Mark: 140
Mechanical - RSen_M_c01_flow_rate: 8.71095 m3/s; RSen_M_c02_flow_rate: 8.71095 m3/s; System Classification: Hydronic Return,Hydronic Supply,Sanitary,Return Air,Supply Air,Power,Controls
Mechanical - Flow - TBQen_M_flow_rate_index: 1; TBQen_M_flow_rate: 8.71095 m3/s; TBQen_M_flow_rate_info: Norm.
Other - Schedule Level: Level: Level 1; ZZZ_V P_c01_plane_Integer: 4; Family: RSen_55_ME_FB_indoor unit - sky air - concealed ceiling-floor_daikin: fdxm60f3v1b9 - slim concealed ceiling unit_daikin_lxwxh 620x1150x200 mm; Family and Type: RSen_55_ME_FB_indoor unit - sky air - concealed ceiling-floor_daikin: fdxm60f3v1b9 - slim concealed ceiling unit_daikin_lxwxh 620x1150x200 mm; Type: RSen_55_ME_FB_indoor unit - sky air - concealed ceiling-floor_daikin: fdxm60f3v1b9 - slim concealed ceiling unit_daikin_lxwxh 620x1150x200 mm; Type Id: RSen_55_ME_FB_indoor unit - sky air - concealed ceiling-floor_daikin: fdxm60f3v1b9 - slim concealed ceiling unit_daikin_lxwxh 620x1150x200 mm; ZZZ_V P_c01_X_Length: 117 mm; ZZZ_V P_c01_Y_Length: -10 mm
Phasing - Phase Created: New Construction
Text - RSen_C_content_manual: https://thorbiq.freshdesk.com/support/solutions

# IfcEnergyConversionDevice: fha140aveb - ceiling suspended unit_daikin_lxwxh 1590x690x235 mm, RSen_55_ME_FB_indoor unit - sky air - cassette-wall-floor_daikin:fha140aveb - ceiling suspended unit_daikin_lxwxh 1590x690x235 mm:2190083
In: Level 1
Type - PredefinedType: AIRCONDITIONINGUNIT; Material: RSen_x_rgb 255 255 255 T00 pure white_gen
Type - Constraints - Default Elevation: 0 mm
Type - Construction - TBQen_C_diameter_type_index: 1; TBQen_C_SOg_ME_02: standard; TBQen_C_accessory_01_index: 0; TBQen_C_diameter_type: OD; TBQen_C_SOg_ME_01: RSen_55_ME_FB_SOg - fha140aveb - SH_daikin_tbq: standard
Type - Dimensions - RSen_C_height: 235 mm; RSen_C_length: 1590 mm; RSen_C_width: 690 mm
Type - Electrical - RSen_E_c01_division_engine: no; RSen_E_c01_load_class: Other; RSen_E_c01_number_of_poles: 1; TBQen_E_c01_power_factor: 1; RSen_E_c01_apparent_power: 0 W; RSen_E_c01_current: 0 A; RSen_E_c01_voltage: 230 V; TBQen_E_c01_power: 0 W
Type - Identity Data - Description: Ceiling suspended; Manufacturer: Daikin Europe N.V.; Model: Sky Air; OmniClass Number: 23.75.10.24.21.27.24; OmniClass Title: Room Air Conditioners; RSen_C_code_article: FHA140AVEB; RSen_C_code_ETIM: Air-conditioning split system – inside unit (evaporator); RSen_C_code_ETIM_URL: https://prod.etim-international.com/Class/Details?classId=EC011580&classVersion=4; RSen_C_code_gtin: -; RSen_C_code_product_class: FHA-A(9); RSen_C_content_creator: © ThorbiQ; RSen_C_content_date_changed: 14/01/2021; RSen_C_content_date_issue: 14/01/2021; RSen_C_content_provider: Daikin Europe N.V.; RSen_C_content_version: 2.0.0; RSen_C_description: Ceiling suspended; RSen_C_model: Sky Air; RSen_C_revit_version: 2018; RSen_C_type: Ceiling suspended unit; RSen_C_type_comments: Indoor unit; TBQ_I BaseKeynote: 55.10.10.10; TBQen_C_code_product: FHA140A; TBQen_C_IFC_version: 2x3; TBQen_C_license: Creative Commons Attribution NoDerivs (CC-ND); TBQen_C_license_info: https://tldrlegal.com/license/creative-commons-attribution-noderivs-(cc-nd)#summary; Type Comments: Indoor unit; Type Name: fha140aveb - ceiling suspended unit_daikin_lxwxh 1590x690x235 mm; URL: www.daikineurope.com
Type - Materials and Finishes - RSen_C_material: RSen_x_rgb 255 255 255 T00 pure white_gen
Type - Mechanical - RSen_P_c03_load_value: 0; TBQ_I Fresh air_percentage intake: 10; RSen_P_c01_volume_flow: 0 m3/s; RSen_P_c02_volume_flow: 0 m3/s; TBQ_I Air flow rate_speed 1: 14.1259 m3/s; TBQ_I Air flow rate_speed 2: 17.0688 m3/s; TBQ_I Air flow rate_speed 3: 20.0116 m3/s
Type - Model Properties - TBQen_C_mounting_ceiling: yes; TBQen_C_mounting_floor: no; TBQen_C_mounting_wall: no
Type - Other - Category: Mechanical Equipment; TBQen_E_c01_yes_no: yes; TBQen_E_c02_yes_no: yes; TBQen_P_c01_yes_no: yes; TBQen_P_c02_yes_no: yes; TBQen_P_c03_yes_no: yes; Family Name: RSen_55_ME_FB_indoor unit - sky air - cassette-wall-floor_daikin; RSen_E_c01_description: c01_el; RSen_E_c02_description: c02_controls; RSen_P_c01_description: c02_liquid piping connection; RSen_P_c01_diameter: 9.52 mm; RSen_P_c02_description: c03_gas piping connection; RSen_P_c02_diameter: 15.9 mm; RSen_P_c03_description: c04_drain piping connection; RSen_P_c03_diameter: 26 mm; TBQen_E_c01_power_factor_state: Lagging; TBQen_E_c01_system_type: Power - Balanced; TBQen_P_c01_diameter_calc: 9.5 mm; TBQen_P_c01_flow_configuration: Preset; TBQen_P_c01_flow_direction: In; TBQen_P_c01_loss_method: Not Defined; TBQen_P_c01_system_classification: Hydronic Supply; TBQen_P_c02_diameter_calc: 15.9 mm; TBQen_P_c02_flow_configuration: Preset; TBQen_P_c02_flow_direction: Out; TBQen_P_c02_loss_method: Not Defined; TBQen_P_c02_system_classification: Hydronic Return; TBQen_P_c03_diameter_calc: 26 mm; TBQen_P_c03_flow_configuration: Fixture Units; TBQen_P_c03_flow_direction: Out; TBQen_P_c03_loss_method: Not Defined; TBQen_P_c03_system_classification: Sanitary
Pset_ManufacturerTypeInformation - Manufacturer: Daikin Europe N.V.
Pset_DistributionFlowElementCommon - Reference: fha140aveb - ceiling suspended unit_daikin_lxwxh 1590x690x235 mm
Constraints - Level: Level: Level 1; Elevation: 2500 mm; Host: Reference Plane : ceiling
Construction - TBQen_C_alignment_index: 0; TBQen_C_GOg: no; TBQen_C_SOg: yes; TBQen_C_alignment: Center; TBQen_C_suspension_height: 20 mm
Dimensions - Area: 45.1723 m2; Volume: 14.7996 m3
Graphics - TBQen_C_clearance_zone: no; TBQen_C_connection_zone: no; TBQen_C_logo: no; TBQen_C_maintenance_zone: no; TBQen_C_neighbour_unit: no; TBQen_C_neighbour_unit_displacement_back: 0 mm; TBQen_C_neighbour_unit_displacement_front: 0 mm; TBQen_C_neighbour_unit_displacement_left: 0 mm; TBQen_C_neighbour_unit_displacement_right: 0 mm
Identity Data - Mark: 132
Mechanical - System Classification: Hydronic Return,Hydronic Supply,Sanitary,Power,Controls
Mechanical - Flow - TBQen_M_flow_rate_index: 1; TBQen_M_flow_rate: 17.0688 m3/s; TBQen_M_flow_rate_info: Norm.
Other - Schedule Level: Level: Level 1; ZZZ_V P_c01_plane_Integer: 3; Family: RSen_55_ME_FB_indoor unit - sky air - cassette-wall-floor_daikin: fha140aveb - ceiling suspended unit_daikin_lxwxh 1590x690x235 mm; Family and Type: RSen_55_ME_FB_indoor unit - sky air - cassette-wall-floor_daikin: fha140aveb - ceiling suspended unit_daikin_lxwxh 1590x690x235 mm; Type: RSen_55_ME_FB_indoor unit - sky air - cassette-wall-floor_daikin: fha140aveb - ceiling suspended unit_daikin_lxwxh 1590x690x235 mm; Type Id: RSen_55_ME_FB_indoor unit - sky air - cassette-wall-floor_daikin: fha140aveb - ceiling suspended unit_daikin_lxwxh 1590x690x235 mm; ZZZ_V P_c01_X_Length: 639 mm; ZZZ_V P_c01_Y_Length: 13.5 mm
Phasing - Phase Created: New Construction
Text - RSen_C_content_manual: https://thorbiq.freshdesk.com/support/solutions

# IfcEnergyConversionDevice: fua71aveb - 4-way blow ceiling suspended unit_daikin_lxwxh 950x950x198 mm, RSen_55_ME_FB_indoor unit - sky air - cassette-wall-floor_daikin:fua71aveb - 4-way blow ceiling suspended unit_daikin_lxwxh 950x950x198 mm:2189933
In: Level 1
Type - PredefinedType: AIRCONDITIONINGUNIT; Material: RSen_x_rgb 255 255 255 T00 pure white_gen
Type - Constraints - Default Elevation: 0 mm
Type - Construction - TBQen_C_diameter_type_index: 1; TBQen_C_SOg_ME_02: standard; TBQen_C_accessory_01_index: 0; TBQen_C_diameter_type: OD; TBQen_C_SOg_ME_01: RSen_55_ME_FB_SOg - fua71aveb - SH_daikin_tbq: standard
Type - Dimensions - RSen_C_height: 198 mm; RSen_C_length: 950 mm; RSen_C_width: 950 mm
Type - Electrical - RSen_E_c01_division_engine: no; RSen_E_c01_load_class: Other; RSen_E_c01_number_of_poles: 1; TBQen_E_c01_power_factor: 1; RSen_E_c01_apparent_power: 0 W; RSen_E_c01_current: 0 A; RSen_E_c01_voltage: 230 V; TBQen_E_c01_power: 0 W
Type - Identity Data - Description: Ceiling suspended; Manufacturer: Daikin Europe N.V.; Model: Sky Air; OmniClass Number: 23.75.10.24.21.27.24; OmniClass Title: Room Air Conditioners; RSen_C_code_article: FUA71AVEB; RSen_C_code_ETIM: Air-conditioning split system – inside unit (evaporator); RSen_C_code_ETIM_URL: https://prod.etim-international.com/Class/Details?classId=EC011580&classVersion=4; RSen_C_code_gtin: -; RSen_C_code_product_class: FUA-A; RSen_C_content_creator: © ThorbiQ; RSen_C_content_date_changed: 14/01/2021; RSen_C_content_date_issue: 14/01/2021; RSen_C_content_provider: Daikin Europe N.V.; RSen_C_content_version: 2.0.0; RSen_C_description: Ceiling suspended; RSen_C_model: Sky Air; RSen_C_revit_version: 2018; RSen_C_type: 4-way blow ceiling suspended unit; RSen_C_type_comments: Indoor unit; TBQ_I BaseKeynote: 55.10.10.10; TBQen_C_code_product: FUA71A; TBQen_C_IFC_version: 2x3; TBQen_C_license: Creative Commons Attribution NoDerivs (CC-ND); TBQen_C_license_info: https://tldrlegal.com/license/creative-commons-attribution-noderivs-(cc-nd)#summary; Type Comments: Indoor unit; Type Name: fua71aveb - 4-way blow ceiling suspended unit_daikin_lxwxh 950x950x198 mm; URL: www.daikineurope.com
Type - Materials and Finishes - RSen_C_material: RSen_x_rgb 255 255 255 T00 pure white_gen
Type - Mechanical - RSen_P_c03_load_value: 0; TBQ_I Fresh air_percentage intake: 0; RSen_P_c01_volume_flow: 0 m3/s; RSen_P_c02_volume_flow: 0 m3/s; TBQ_I Air flow rate_speed 1: 9.41724 m3/s; TBQ_I Air flow rate_speed 2: 11.4773 m3/s; TBQ_I Air flow rate_speed 3: 13.5373 m3/s
Type - Model Properties - TBQen_C_mounting_ceiling: yes; TBQen_C_mounting_floor: no; TBQen_C_mounting_wall: no
Type - Other - Category: Mechanical Equipment; TBQen_E_c01_yes_no: yes; TBQen_E_c02_yes_no: yes; TBQen_P_c01_yes_no: yes; TBQen_P_c02_yes_no: yes; TBQen_P_c03_yes_no: yes; Family Name: RSen_55_ME_FB_indoor unit - sky air - cassette-wall-floor_daikin; RSen_E_c01_description: c01_el; RSen_E_c02_description: c02_controls; RSen_P_c01_description: c02_liquid piping connection; RSen_P_c01_diameter: 9.52 mm; RSen_P_c02_description: c03_gas piping connection; RSen_P_c02_diameter: 15.9 mm; RSen_P_c03_description: c04_drain piping connection; RSen_P_c03_diameter: 32 mm; TBQen_E_c01_power_factor_state: Lagging; TBQen_E_c01_system_type: Power - Balanced; TBQen_P_c01_diameter_calc: 9.5 mm; TBQen_P_c01_flow_configuration: Preset; TBQen_P_c01_flow_direction: In; TBQen_P_c01_loss_method: Not Defined; TBQen_P_c01_system_classification: Hydronic Supply; TBQen_P_c02_diameter_calc: 15.9 mm; TBQen_P_c02_flow_configuration: Preset; TBQen_P_c02_flow_direction: Out; TBQen_P_c02_loss_method: Not Defined; TBQen_P_c02_system_classification: Hydronic Return; TBQen_P_c03_diameter_calc: 32 mm; TBQen_P_c03_flow_configuration: Fixture Units; TBQen_P_c03_flow_direction: Out; TBQen_P_c03_loss_method: Not Defined; TBQen_P_c03_system_classification: Sanitary
Pset_ManufacturerTypeInformation - Manufacturer: Daikin Europe N.V.
Pset_DistributionFlowElementCommon - Reference: fua71aveb - 4-way blow ceiling suspended unit_daikin_lxwxh 950x950x198 mm
Constraints - Level: Level: Level 1; Elevation: 2500 mm; Host: Reference Plane : ceiling
Construction - TBQen_C_alignment_index: 0; TBQen_C_GOg: no; TBQen_C_SOg: yes; TBQen_C_alignment: Center; TBQen_C_suspension_height: 20 mm
Dimensions - Area: 61.225 m2; Volume: 45.4908 m3
Graphics - TBQen_C_clearance_zone: no; TBQen_C_connection_zone: no; TBQen_C_logo: no; TBQen_C_maintenance_zone: no; TBQen_C_neighbour_unit: no; TBQen_C_neighbour_unit_displacement_back: 0 mm; TBQen_C_neighbour_unit_displacement_front: 0 mm; TBQen_C_neighbour_unit_displacement_left: 0 mm; TBQen_C_neighbour_unit_displacement_right: 0 mm
Identity Data - Mark: 131
Mechanical - System Classification: Hydronic Return,Hydronic Supply,Sanitary,Power,Controls
Mechanical - Flow - TBQen_M_flow_rate_index: 1; TBQen_M_flow_rate: 11.4773 m3/s; TBQen_M_flow_rate_info: Norm.
Other - Schedule Level: Level: Level 1; ZZZ_V P_c01_plane_Integer: 5; Family: RSen_55_ME_FB_indoor unit - sky air - cassette-wall-floor_daikin: fua71aveb - 4-way blow ceiling suspended unit_daikin_lxwxh 950x950x198 mm; Family and Type: RSen_55_ME_FB_indoor unit - sky air - cassette-wall-floor_daikin: fua71aveb - 4-way blow ceiling suspended unit_daikin_lxwxh 950x950x198 mm; Type: RSen_55_ME_FB_indoor unit - sky air - cassette-wall-floor_daikin: fua71aveb - 4-way blow ceiling suspended unit_daikin_lxwxh 950x950x198 mm; Type Id: RSen_55_ME_FB_indoor unit - sky air - cassette-wall-floor_daikin: fua71aveb - 4-way blow ceiling suspended unit_daikin_lxwxh 950x950x198 mm; ZZZ_V P_c01_X_Length: 316 mm; ZZZ_V P_c01_Y_Length: -11 mm
Phasing - Phase Created: New Construction
Text - RSen_C_content_manual: https://thorbiq.freshdesk.com/support/solutions

# IfcEnergyConversionDevice: fwe10c5tv1b - concealed ceiling unit with low esp_daikin_lxwxh 590x1780x247 mm, RSen_55_ME_FB_fan coils - concealed ceiling-flexi type - 2 pipes_daikin:fwe10c5tv1b - concealed ceiling unit with low esp_daikin_lxwxh 590x1780x247 mm:1865688
In: Level 1
Type - PredefinedType: WATERHEATINGCOIL; Material: RSen_x_rgb 199 235 223 T00 galvanised steel plate_gen
Type - Constraints - Default Elevation: 0 mm
Type - Construction - TBQen_C_diameter_type_index: 1; TBQen_C_SOg_ME_02: standard; TBQen_C_accessory_01_index: 0; TBQen_C_diameter_type: OD; TBQen_C_SOg_ME_01: RSen_55_ME_FB_SOg - fwe10c5tv1b - left - SH_daikin_tbq: standard
Type - Dimensions - RSen_C_height: 247 mm; RSen_C_length: 590 mm; RSen_C_width: 1780 mm
Type - Electrical - RSen_E_c01_load_class: Other; RSen_E_c01_number_of_poles: 1; TBQen_E_c01_power_factor: 1; RSen_E_c01_apparent_power: 230 W; RSen_E_c01_current: 0 A; RSen_E_c01_division_engine: yes; RSen_E_c01_voltage: 230 V; TBQen_E_c01_power: 230 W
Type - Identity Data - Description: Cooling Only, Heating Only; Manufacturer: Daikin Europe N.V.; Model: Fan Coil; OmniClass Number: 23.75.70.17.27; OmniClass Title: Fan Coil Units; RSen_C_code_article: FWE10C5TV1B; RSen_C_code_ETIM: Air-conditioning split system – inside unit (evaporator); RSen_C_code_ETIM_URL: https://prod.etim-international.com/Class/Details?classId=EC011580&classVersion=4; RSen_C_code_product_class: FWE-CT; RSen_C_content_creator: © ThorbiQ; RSen_C_content_date_changed: 14/01/2021; RSen_C_content_date_issue: 14/01/2021; RSen_C_content_provider: Daikin Europe N.V.; RSen_C_content_version: 2.0.0; RSen_C_description: Cooling Only, Heating Only; RSen_C_model: Fan Coil; RSen_C_revit_version: 2018; RSen_C_type: Concealed ceiling unit with low ESP; RSen_C_type_comments: Indoor unit; TBQ_I BaseKeynote: 55.10.10.10; TBQen_C_code_product: FWE10CT; TBQen_C_IFC_version: 2x3; TBQen_C_license: Creative Commons Attribution NoDerivs (CC-ND); TBQen_C_license_info: https://tldrlegal.com/license/creative-commons-attribution-noderivs-(cc-nd)#summary; Type Name: fwe10c5tv1b - concealed ceiling unit with low esp_daikin_lxwxh 590x1780x247 mm; URL: www.daikineurope.com
Type - Materials and Finishes - RSen_C_material: RSen_x_rgb 199 235 223 T00 galvanised steel plate_gen
Type - Mechanical - RSen_P_c01_volume_flow: 0 m3/s; RSen_P_c02_volume_flow: 0 m3/s; RSen_P_c05_load_value: 0; TBQ_I Air flow rate_speed 1: 7.92618 m3/s; TBQ_I Air flow rate_speed 2: 11.7912 m3/s; TBQ_I Air flow rate_speed 3: 17.0197 m3/s; TBQ_I Fresh air_percentage intake: 0
Type - Model Properties - TBQen_C_mounting_ceiling: yes; TBQen_C_mounting_floor: no; TBQen_C_mounting_wall: no
Type - Other - Category: Mechanical Equipment; TBQen_E_c01_yes_no: yes; TBQen_P_c01_yes_no: yes; TBQen_P_c02_yes_no: yes; TBQen_P_c05_yes_no: yes; TBQen_M_c01_yes_no: yes; TBQen_M_c02_yes_no: yes; RSen_M_c01_diameter: 0 mm; RSen_M_c02_diameter: 0 mm; Family Name: RSen_55_ME_FB_fan coils - concealed ceiling-flexi type - 2 pipes_daikin; RSen_E_c01_description: c01_el; RSen_E_c02_description: c02_controls; RSen_M_c01_description: c01_return air; RSen_M_c01_height: 207 mm; RSen_M_c01_width: 1569 mm; RSen_M_c02_description: c02_supply air; RSen_M_c02_height: 125 mm; RSen_M_c02_width: 1569 mm; RSen_P_c01_description: c01_water pipe connection; RSen_P_c01_diameter: 20 mm; RSen_P_c02_description: c02_water pipe connection; RSen_P_c02_diameter: 20 mm; RSen_P_c05_description: c05_drain piping connection; RSen_P_c05_diameter: 20 mm; TBQen_E_c01_power_factor_state: Lagging; TBQen_E_c01_system_type: Power - Balanced; TBQen_E_c02_yes_no: no; TBQen_M_c01_flow_configuration: Preset; TBQen_M_c01_flow_direction: in; TBQen_M_c01_loss_method: Not Defined; TBQen_M_c01_optional: no; TBQen_M_c01_shape: Rectangular; TBQen_M_c01_system_classification: Return Air; TBQen_M_c02_flow_configuration: Preset; TBQen_M_c02_flow_direction: Out; TBQen_M_c02_loss_method: Not Defined; TBQen_M_c02_optional: no; TBQen_M_c02_shape: Rectangular; TBQen_M_c02_system_classification: Supply Air; TBQen_P_c01_diameter_calc: 20 mm; TBQen_P_c01_flow_configuration: Preset; TBQen_P_c01_flow_direction: In; TBQen_P_c01_loss_method: Not Defined; TBQen_P_c01_system_classification: Hydronic Supply; TBQen_P_c02_diameter_calc: 20 mm; TBQen_P_c02_flow_configuration: Preset; TBQen_P_c02_flow_direction: Out; TBQen_P_c02_loss_method: Not Defined; TBQen_P_c02_system_classification: Hydronic Return; TBQen_P_c05_diameter_calc: 20 mm; TBQen_P_c05_flow_configuration: Fixture Units; TBQen_P_c05_flow_direction: Out; TBQen_P_c05_loss_method: Not Defined; TBQen_P_c05_system_classification: Sanitary
Pset_ManufacturerTypeInformation - Manufacturer: Daikin Europe N.V.
Pset_DistributionFlowElementCommon - Reference: fwe10c5tv1b - concealed ceiling unit with low esp_daikin_lxwxh 590x1780x247 mm
Constraints - Level: Level: Level 1; Elevation: 2500 mm; Host: Reference Plane : ceiling
Construction - TBQen_C_alignment_index: 0; TBQen_C_GOg: no; TBQen_C_SOg: yes; TBQen_C_alignment: Center; TBQen_C_suspension_height: 20 mm
Dimensions - Area: 40.0595 m2; Volume: 6.25745 m3
Graphics - TBQen_C_clearance_zone: no; TBQen_C_connection_zone: no; TBQen_C_logo: no; TBQen_C_maintenance_zone: no; TBQen_C_neighbour_unit: no; TBQen_C_neighbour_unit_displacement_back: 0 mm; TBQen_C_neighbour_unit_displacement_front: 0 mm; TBQen_C_neighbour_unit_displacement_left: 0 mm; TBQen_C_neighbour_unit_displacement_right: 0 mm
Identity Data - Mark: 118
Mechanical - RSen_M_c01_flow_rate: 11.7912 m3/s; RSen_M_c02_flow_rate: 11.7912 m3/s; System Classification: Hydronic Supply,Hydronic Return,Return Air,Supply Air,Power,Controls,Sanitary
Mechanical - Flow - TBQen_M_flow_rate: 11.7912 m3/s; TBQen_M_flow_rate_index: 1; TBQen_M_flow_rate_info: Norm.
Other - Schedule Level: Level: Level 1; ZZZ_V P_c01_plane_Integer: 4; Family: RSen_55_ME_FB_fan coils - concealed ceiling-flexi type - 2 pipes_daikin: fwe10c5tv1b - concealed ceiling unit with low esp_daikin_lxwxh 590x1780x247 mm; Family and Type: RSen_55_ME_FB_fan coils - concealed ceiling-flexi type - 2 pipes_daikin: fwe10c5tv1b - concealed ceiling unit with low esp_daikin_lxwxh 590x1780x247 mm; Type: RSen_55_ME_FB_fan coils - concealed ceiling-flexi type - 2 pipes_daikin: fwe10c5tv1b - concealed ceiling unit with low esp_daikin_lxwxh 590x1780x247 mm; Type Id: RSen_55_ME_FB_fan coils - concealed ceiling-flexi type - 2 pipes_daikin: fwe10c5tv1b - concealed ceiling unit with low esp_daikin_lxwxh 590x1780x247 mm; ZZZ_V P_c01_X_Length: -137.5 mm; ZZZ_V P_c01_Y_Length: 54 mm
Phasing - Phase Created: New Construction
Text - RSen_C_content_manual: https://thorbiq.freshdesk.com/support/solutions

# IfcEnergyConversionDevice: fwf05b5tv1b - 4-way blow ceiling mounted cassette_daikin_lxwxh 700x700x315 mm, RSen_55_ME_FB_fan coils - exposed cassette - 2 pipes - fresh air intake_daikin:fwf05b5tv1b - 4-way blow ceiling mounted cassette_daikin_lxwxh 700x700x315 mm:1924095
In: Level 1
Type - PredefinedType: WATERHEATINGCOIL; Material: RSen_x_rgb 255 255 255 T00 pure white_gen
Type - Constraints - Default Elevation: 0 mm
Type - Construction - TBQen_C_diameter_type_index: 1; TBQen_C_SOg_ME_02: standard; TBQen_C_accessory_01_index: 0; TBQen_C_diameter_type: OD; TBQen_C_SOg_ME_01: RSen_55_ME_FB_SOg - fwf05b5tv1b - SH_daikin_tbq: standard
Type - Dimensions - RSen_C_height: 315 mm; RSen_C_length: 700 mm; RSen_C_width: 700 mm
Type - Electrical - RSen_E_c01_load_class: Other; RSen_E_c01_number_of_poles: 1; TBQen_E_c01_power_factor: 1; RSen_E_c01_division_engine: yes; RSen_E_c01_apparent_power: 0 W; RSen_E_c01_current: 0 A; RSen_E_c01_voltage: 230 V; TBQen_E_c01_power: 0 W
Type - Identity Data - Description: Cooling Only, Heating Only; Manufacturer: Daikin Europe N.V.; Model: Fan Coil; OmniClass Number: 23.75.70.17.27; OmniClass Title: Fan Coil Units; RSen_C_code_article: FWF05B5TV1B; RSen_C_code_ETIM: Air-conditioning split system – inside unit (evaporator); RSen_C_code_ETIM_URL: https://prod.etim-international.com/Class/Details?classId=EC011580&classVersion=4; RSen_C_code_product_class: FWF-BT; RSen_C_content_creator: © ThorbiQ; RSen_C_content_date_changed: 14/01/2021; RSen_C_content_date_issue: 14/01/2021; RSen_C_content_provider: Daikin Europe N.V.; RSen_C_content_version: 2.0.0; RSen_C_description: Cooling Only, Heating Only; RSen_C_model: Fan Coil; RSen_C_revit_version: 2018; RSen_C_type: 4-way blow ceiling mounted cassette; RSen_C_type_comments: Indoor unit; TBQ_I BaseKeynote: 55.10.10.10; TBQen_C_code_product: FWF05BT; TBQen_C_IFC_version: 2x3; TBQen_C_license: Creative Commons Attribution NoDerivs (CC-ND); TBQen_C_license_info: https://tldrlegal.com/license/creative-commons-attribution-noderivs-(cc-nd)#summary; Type Name: fwf05b5tv1b - 4-way blow ceiling mounted cassette_daikin_lxwxh 700x700x315 mm; URL: www.daikineurope.com
Type - Materials and Finishes - RSen_C_material: RSen_x_rgb 255 255 255 T00 pure white_gen
Type - Mechanical - RSen_P_c05_load_value: 0; RSen_P_c01_volume_flow: 0 m3/s; RSen_P_c02_volume_flow: 0 m3/s; TBQ_I Air flow rate_speed 1: 0 m3/s; TBQ_I Air flow rate_speed 2: 0 m3/s; TBQ_I Air flow rate_speed 3: 0 m3/s; TBQ_I Fresh air_percentage intake: 10
Type - Model Properties - TBQen_C_mounting_ceiling: yes; TBQen_C_mounting_floor: no; TBQen_C_mounting_wall: no
Type - Other - Category: Mechanical Equipment; TBQen_E_c01_yes_no: yes; TBQen_P_c01_yes_no: yes; TBQen_P_c02_yes_no: yes; TBQen_P_c05_yes_no: yes; RSen_M_c03_height: 0 mm; RSen_M_c03_width: 0 mm; TBQen_M_c03_yes_no: yes; TBQen_E_c02_yes_no: no; Family Name: RSen_55_ME_FB_fan coils - exposed cassette - 2 pipes - fresh air intake_daikin; RSen_E_c01_description: c01_el; RSen_E_c02_description: c02_controls; RSen_M_c03_description: c01_air inlet; RSen_M_c03_diameter: 100 mm; RSen_P_c01_description: c01_water pipe connection; RSen_P_c01_diameter: 20 mm; RSen_P_c02_description: c02_water pipe connection; RSen_P_c02_diameter: 20 mm; RSen_P_c05_description: c03_drain piping connection; RSen_P_c05_diameter: 26 mm; TBQen_E_c01_power_factor_state: Lagging; TBQen_E_c01_system_type: Power - Balanced; TBQen_M_c03_flow_configuration: Preset; TBQen_M_c03_flow_direction: In; TBQen_M_c03_loss_method: Not Defined; TBQen_M_c03_optional: yes; TBQen_M_c03_shape: Round; TBQen_M_c03_system_classification: Supply Air; TBQen_P_c01_diameter_calc: 20 mm; TBQen_P_c01_flow_configuration: Preset; TBQen_P_c01_flow_direction: In; TBQen_P_c01_loss_method: Not Defined; TBQen_P_c01_system_classification: Hydronic Supply; TBQen_P_c02_diameter_calc: 20 mm; TBQen_P_c02_flow_configuration: Preset; TBQen_P_c02_flow_direction: Out; TBQen_P_c02_loss_method: Not Defined; TBQen_P_c02_system_classification: Hydronic Return; TBQen_P_c05_diameter_calc: 26 mm; TBQen_P_c05_flow_configuration: Fixture Units; TBQen_P_c05_flow_direction: Out; TBQen_P_c05_loss_method: Not Defined; TBQen_P_c05_system_classification: Sanitary
Pset_ManufacturerTypeInformation - Manufacturer: Daikin Europe N.V.
Pset_DistributionFlowElementCommon - Reference: fwf05b5tv1b - 4-way blow ceiling mounted cassette_daikin_lxwxh 700x700x315 mm
Constraints - Level: Level: Level 1; Elevation: 2500 mm; Host: Reference Plane : ceiling
Construction - TBQen_C_alignment_index: 0; TBQen_C_GOg: no; TBQen_C_SOg: yes; TBQen_C_alignment: Center; TBQen_C_suspension_height: 20 mm
Dimensions - Area: 54.5598 m2; Volume: 41.8706 m3
Graphics - TBQen_C_clearance_zone: no; TBQen_C_connection_zone: no; TBQen_C_logo: no; TBQen_C_maintenance_zone: no; TBQen_C_neighbour_unit: no; TBQen_C_neighbour_unit_displacement_back: 0 mm; TBQen_C_neighbour_unit_displacement_front: 0 mm; TBQen_C_neighbour_unit_displacement_left: 0 mm; TBQen_C_neighbour_unit_displacement_right: 0 mm
Identity Data - Mark: 121
Mechanical - RSen_M_c03_flow_rate: 0 m3/s; System Classification: Hydronic Supply,Hydronic Return,Supply Air,Power,Controls,Sanitary
Mechanical - Flow - TBQen_M_flow_rate_index: 1; TBQen_M_flow_rate: 0 m3/s; TBQen_M_flow_rate_info: Norm.
Other - Schedule Level: Level: Level 1; Family: RSen_55_ME_FB_fan coils - exposed cassette - 2 pipes - fresh air intake_daikin: fwf05b5tv1b - 4-way blow ceiling mounted cassette_daikin_lxwxh 700x700x315 mm; Family and Type: RSen_55_ME_FB_fan coils - exposed cassette - 2 pipes - fresh air intake_daikin: fwf05b5tv1b - 4-way blow ceiling mounted cassette_daikin_lxwxh 700x700x315 mm; Type: RSen_55_ME_FB_fan coils - exposed cassette - 2 pipes - fresh air intake_daikin: fwf05b5tv1b - 4-way blow ceiling mounted cassette_daikin_lxwxh 700x700x315 mm; Type Id: RSen_55_ME_FB_fan coils - exposed cassette - 2 pipes - fresh air intake_daikin: fwf05b5tv1b - 4-way blow ceiling mounted cassette_daikin_lxwxh 700x700x315 mm; ZZZ_V P_c01_plane_Integer: 3; ZZZ_V P_c01_X_Length: -217 mm; ZZZ_V P_c01_Y_Length: -19.5 mm
Phasing - Phase Created: New Construction
Text - RSen_C_content_manual: https://thorbiq.freshdesk.com/support/solutions

# IfcEnergyConversionDevice: fxfn112a2veb - round flow cassette - designer panel_daikin_lxwxh 950x950x385 mm, RSen_55_ME_FB_indoor unit - refrigeration - cassette - fresh air intake_daikin:fxfn112a2veb - round flow cassette - designer panel_daikin_lxwxh 950x950x385 mm:2409422
In: Level 1
Type - PredefinedType: AIRCONDITIONINGUNIT; Material: RSen_x_rgb 255 255 255 T00 pure white_gen
Type - Constraints - Default Elevation: 0 mm
Type - Construction - TBQen_C_diameter_type_index: 1; TBQen_C_SOg_ME_02: standard; TBQen_C_accessory_01_index: 0; TBQen_C_diameter_type: OD; TBQen_C_SOg_ME_01: RSen_55_ME_FB_SOg - fxfn112a2veb - designer panel - SH_daikin_tbq: standard
Type - Dimensions - RSen_C_height: 385 mm; RSen_C_length: 950 mm; RSen_C_width: 950 mm
Type - Electrical - RSen_E_c01_division_engine: no; RSen_E_c01_load_class: Other; RSen_E_c01_number_of_poles: 1; TBQen_E_c01_power_factor: 1; RSen_E_c01_apparent_power: 96 W; RSen_E_c01_current: 0 A; RSen_E_c01_voltage: 230 V; TBQen_E_c01_power: 96 W
Type - Identity Data - Description: Refrigeration; Manufacturer: Daikin Europe N.V.; Model: Conveni-pack; OmniClass Number: 23.40.40.11.11.11; OmniClass Title: Refrigerators; RSen_C_code_article: FXFN112A2VEB; RSen_C_code_ETIM: Air-conditioning split system – inside unit (evaporator); RSen_C_code_ETIM_URL: https://prod.etim-international.com/Class/Details?classId=EC011580&classVersion=4; RSen_C_code_gtin: -; RSen_C_code_product_class: FXFN-A2; RSen_C_content_creator: © ThorbiQ; RSen_C_content_date_changed: 11/11/2021; RSen_C_content_date_issue: 11/11/2021; RSen_C_content_provider: Daikin Europe N.V.; RSen_C_content_version: 2.0.0; RSen_C_description: Refrigeration; RSen_C_model: Conveni-pack; RSen_C_revit_version: 2019; RSen_C_type: Round flow cassette; RSen_C_type_comments: Indoor unit; TBQ_I BaseKeynote: 55.10.10.10; TBQen_C_code_product: FXFN112A2; TBQen_C_IFC_version: 2x3; TBQen_C_license: Creative Commons Attribution NoDerivs (CC-ND); TBQen_C_license_info: https://tldrlegal.com/license/creative-commons-attribution-noderivs-(cc-nd)#summary; Type Comments: Indoor unit; Type Name: fxfn112a2veb - round flow cassette - designer panel_daikin_lxwxh 950x950x385 mm; URL: www.daikineurope.com
Type - Materials and Finishes - RSen_C_material: RSen_x_rgb 255 255 255 T00 pure white_gen
Type - Mechanical - RSen_P_c03_load_value: 0; TBQ_I Fresh air_percentage intake: 10; RSen_P_c01_volume_flow: 0 m3/s; RSen_P_c02_volume_flow: 0 m3/s; TBQ_I Air flow rate_speed 1: 12.1247 m3/s; TBQ_I Air flow rate_speed 2: 15.715 m3/s; TBQ_I Air flow rate_speed 3: 19.2465 m3/s
Type - Model Properties - TBQen_C_mounting_ceiling: yes; TBQen_C_mounting_floor: no; TBQen_C_mounting_wall: no
Type - Other - Category: Mechanical Equipment; TBQen_E_c01_yes_no: yes; TBQen_E_c02_yes_no: yes; TBQen_P_c01_yes_no: yes; TBQen_P_c02_yes_no: yes; TBQen_P_c03_yes_no: yes; RSen_M_c03_height: 0 mm; RSen_M_c03_width: 0 mm; TBQen_M_c03_yes_no: yes; TBQen_M_c03_optional: yes; Family Name: RSen_55_ME_FB_indoor unit - refrigeration - cassette - fresh air intake_daikin; RSen_E_c01_description: c01_el; RSen_E_c02_description: c02_controls; RSen_M_c03_description: c03_air inlet; RSen_M_c03_diameter: 75 mm; RSen_P_c01_description: c01_liquid piping connection; RSen_P_c01_diameter: 9.52 mm; RSen_P_c02_description: c02_gas piping connection; RSen_P_c02_diameter: 15.9 mm; RSen_P_c03_description: c03_drain piping connection; RSen_P_c03_diameter: 32 mm; TBQen_E_c01_power_factor_state: Lagging; TBQen_E_c01_system_type: Power - Balanced; TBQen_M_c03_flow_configuration: Preset; TBQen_M_c03_flow_direction: In; TBQen_M_c03_loss_method: Not Defined; TBQen_M_c03_shape: Round; TBQen_M_c03_system_classification: Supply Air; TBQen_P_c01_diameter_calc: 9.5 mm; TBQen_P_c01_flow_configuration: Preset; TBQen_P_c01_flow_direction: In; TBQen_P_c01_loss_method: Not Defined; TBQen_P_c01_system_classification: Hydronic Supply; TBQen_P_c02_diameter_calc: 15.9 mm; TBQen_P_c02_flow_configuration: Preset; TBQen_P_c02_flow_direction: Out; TBQen_P_c02_loss_method: Not Defined; TBQen_P_c02_system_classification: Hydronic Return; TBQen_P_c03_diameter_calc: 32 mm; TBQen_P_c03_flow_configuration: Fixture Units; TBQen_P_c03_flow_direction: Out; TBQen_P_c03_loss_method: Not Defined; TBQen_P_c03_system_classification: Sanitary
Pset_ManufacturerTypeInformation - Manufacturer: Daikin Europe N.V.
Pset_DistributionFlowElementCommon - Reference: fxfn112a2veb - round flow cassette - designer panel_daikin_lxwxh 950x950x385 mm
Constraints - Level: Level: Level 1; Elevation: 2500 mm; Host: Reference Plane : ceiling
Construction - TBQen_C_alignment_index: 0; TBQen_C_GOg: no; TBQen_C_SOg: yes; TBQen_C_alignment: Center; TBQen_C_suspension_height: 20 mm
Dimensions - Area: 73.5869 m2; Volume: 55.5623 m3
Graphics - TBQen_C_clearance_zone: no; TBQen_C_connection_zone: no; TBQen_C_logo: no; TBQen_C_maintenance_zone: no; TBQen_C_neighbour_unit: no; TBQen_C_neighbour_unit_displacement_back: 0 mm; TBQen_C_neighbour_unit_displacement_front: 0 mm; TBQen_C_neighbour_unit_displacement_left: 0 mm; TBQen_C_neighbour_unit_displacement_right: 0 mm
Identity Data - Mark: 156
Mechanical - RSen_M_c03_flow_rate: 1.5715 m3/s; System Classification: Hydronic Return,Hydronic Supply,Sanitary,Supply Air,Power,Controls
Mechanical - Flow - TBQen_M_flow_rate_index: 1; TBQen_M_flow_rate: 15.715 m3/s; TBQen_M_flow_rate_info: Norm.
Other - Schedule Level: Level: Level 1; ZZZ_V P_c01_plane_Integer: 3; Family: RSen_55_ME_FB_indoor unit - refrigeration - cassette - fresh air intake_daikin: fxfn112a2veb - round flow cassette - designer panel_daikin_lxwxh 950x950x385 mm; Family and Type: RSen_55_ME_FB_indoor unit - refrigeration - cassette - fresh air intake_daikin: fxfn112a2veb - round flow cassette - designer panel_daikin_lxwxh 950x950x385 mm; Type: RSen_55_ME_FB_indoor unit - refrigeration - cassette - fresh air intake_daikin: fxfn112a2veb - round flow cassette - designer panel_daikin_lxwxh 950x950x385 mm; Type Id: RSen_55_ME_FB_indoor unit - refrigeration - cassette - fresh air intake_daikin: fxfn112a2veb - round flow cassette - designer panel_daikin_lxwxh 950x950x385 mm; ZZZ_V P_c01_X_Length: -280 mm; ZZZ_V P_c01_Y_Length: -4.5 mm
Phasing - Phase Created: New Construction
Text - RSen_C_content_manual: https://thorbiq.freshdesk.com/support/solutions

# IfcEnergyConversionDevice: fxsn112a2veb - concealed ceiling unit_daikin_lxwxh 800x1400x245 mm, RSen_55_ME_FB_indoor unit - refrigeration - concealed - fresh air intake_daikin:fxsn112a2veb - concealed ceiling unit_daikin_lxwxh 800x1400x245 mm:2461998
In: Level 1
Type - PredefinedType: AIRCONDITIONINGUNIT; Material: RSen_x_rgb 255 255 255 T00 pure white_gen
Type - Constraints - Default Elevation: 0 mm
Type - Construction - TBQen_C_diameter_type_index: 1; TBQen_C_SOg_ME_02: standard; TBQen_C_accessory_01_index: 0; TBQen_C_diameter_type: OD; TBQen_C_SOg_ME_01: RSen_55_ME_FB_SOg - fxsn112a2veb - SH_daikin_tbq: standard
Type - Dimensions - RSen_C_height: 245 mm; RSen_C_length: 800 mm; RSen_C_width: 1400 mm
Type - Electrical - RSen_E_c01_division_engine: no; RSen_E_c01_load_class: Other; RSen_E_c01_number_of_poles: 1; TBQen_E_c01_power_factor: 1; RSen_E_c01_apparent_power: 388 W; RSen_E_c01_current: 0 A; RSen_E_c01_voltage: 230 V; TBQen_E_c01_power: 388 W
Type - Identity Data - Description: Refrigeration; Manufacturer: Daikin Europe N.V.; Model: Conveni-pack; OmniClass Number: 23.40.40.11.11.11; OmniClass Title: Refrigerators; RSen_C_code_article: FXSN112A2VEB; RSen_C_code_ETIM: Air-conditioning split system – inside unit (evaporator); RSen_C_code_ETIM_URL: https://prod.etim-international.com/Class/Details?classId=EC011580&classVersion=4; RSen_C_code_gtin: -; RSen_C_code_product_class: FXSN-A2; RSen_C_content_creator: © ThorbiQ; RSen_C_content_date_changed: 14/01/2021; RSen_C_content_date_issue: 14/01/2021; RSen_C_content_provider: Daikin Europe N.V.; RSen_C_content_version: 2.0.0; RSen_C_description: Refrigeration; RSen_C_model: Conveni-pack; RSen_C_revit_version: 2018; RSen_C_type: Concealed ceiling unit; RSen_C_type_comments: Indoor unit; TBQ_I BaseKeynote: 55.10.10.10; TBQen_C_code_product: FXSN112A2; TBQen_C_IFC_version: 2x3; TBQen_C_license: Creative Commons Attribution NoDerivs (CC-ND); TBQen_C_license_info: https://tldrlegal.com/license/creative-commons-attribution-noderivs-(cc-nd)#summary; Type Comments: Indoor unit; Type Name: fxsn112a2veb - concealed ceiling unit_daikin_lxwxh 800x1400x245 mm; URL: www.daikineurope.com
Type - Materials and Finishes - RSen_C_material: RSen_x_rgb 255 255 255 T00 pure white_gen
Type - Mechanical - RSen_P_c03_load_value: 0; TBQ_I Fresh air_percentage intake: 10; RSen_P_c01_volume_flow: 0 m3/s; RSen_P_c02_volume_flow: 0 m3/s; TBQ_I Air flow rate_speed 1: 15.303 m3/s; TBQ_I Air flow rate_speed 2: 18.5402 m3/s; TBQ_I Air flow rate_speed 3: 21.1888 m3/s
Type - Model Properties - TBQen_C_mounting_ceiling: yes; TBQen_C_mounting_floor: no; TBQen_C_mounting_wall: no
Type - Other - Category: Mechanical Equipment; TBQen_E_c01_yes_no: yes; TBQen_E_c02_yes_no: yes; TBQen_P_c01_yes_no: yes; TBQen_P_c02_yes_no: yes; TBQen_P_c03_yes_no: yes; RSen_M_c03_height: 0 mm; RSen_M_c03_width: 0 mm; TBQen_M_c01_yes_no: yes; TBQen_M_c02_yes_no: yes; TBQen_M_c03_yes_no: yes; RSen_M_c01_diameter: 0 mm; RSen_M_c02_diameter: 0 mm; TBQen_M_c01_optional: no; TBQen_M_c02_optional: no; TBQen_M_c03_optional: yes; Family Name: RSen_55_ME_FB_indoor unit - refrigeration - concealed - fresh air intake_daikin; RSen_E_c01_description: c01_el; RSen_E_c02_description: c02_controls; RSen_M_c01_description: c01_return air; RSen_M_c01_height: 210 mm; RSen_M_c01_width: 1354 mm; RSen_M_c02_description: c02_supply air; RSen_M_c02_height: 178 mm; RSen_M_c02_width: 1192 mm; RSen_M_c03_description: c03_air inlet; RSen_M_c03_diameter: 100 mm; RSen_P_c01_description: c01_liquid piping connection; RSen_P_c01_diameter: 9.52 mm; RSen_P_c02_description: c02_gas piping connection; RSen_P_c02_diameter: 12.7 mm; RSen_P_c03_description: c03_drain piping connection; RSen_P_c03_diameter: 26 mm; TBQen_E_c01_power_factor_state: Lagging; TBQen_E_c01_system_type: Power - Balanced; TBQen_M_c01_flow_configuration: Preset; TBQen_M_c01_flow_direction: in; TBQen_M_c01_loss_method: Not Defined; TBQen_M_c01_shape: Rectangular; TBQen_M_c01_system_classification: Return Air; TBQen_M_c02_flow_configuration: Preset; TBQen_M_c02_flow_direction: Out; TBQen_M_c02_loss_method: Not Defined; TBQen_M_c02_shape: Rectangular; TBQen_M_c02_system_classification: Supply Air; TBQen_M_c03_flow_configuration: Preset; TBQen_M_c03_flow_direction: In; TBQen_M_c03_loss_method: Not Defined; TBQen_M_c03_shape: Round; TBQen_M_c03_system_classification: Supply Air; TBQen_P_c01_diameter_calc: 9.5 mm; TBQen_P_c01_flow_configuration: Preset; TBQen_P_c01_flow_direction: In; TBQen_P_c01_loss_method: Not Defined; TBQen_P_c01_system_classification: Hydronic Supply; TBQen_P_c02_diameter_calc: 12.7 mm; TBQen_P_c02_flow_configuration: Preset; TBQen_P_c02_flow_direction: Out; TBQen_P_c02_loss_method: Not Defined; TBQen_P_c02_system_classification: Hydronic Return; TBQen_P_c03_diameter_calc: 26 mm; TBQen_P_c03_flow_configuration: Fixture Units; TBQen_P_c03_flow_direction: Out; TBQen_P_c03_loss_method: Not Defined; TBQen_P_c03_system_classification: Sanitary
Pset_ManufacturerTypeInformation - Manufacturer: Daikin Europe N.V.
Pset_DistributionFlowElementCommon - Reference: fxsn112a2veb - concealed ceiling unit_daikin_lxwxh 800x1400x245 mm
Constraints - Level: Level: Level 1; Elevation: 2500 mm; Host: Reference Plane : ceiling
Construction - TBQen_C_alignment_index: 0; TBQen_C_GOg: no; TBQen_C_SOg: yes; TBQen_C_alignment: Center; TBQen_C_suspension_height: 20 mm
Dimensions - Area: 39.9859 m2; Volume: 6.51022 m3
Graphics - TBQen_C_clearance_zone: no; TBQen_C_connection_zone: no; TBQen_C_logo: no; TBQen_C_maintenance_zone: no; TBQen_C_neighbour_unit: no; TBQen_C_neighbour_unit_displacement_back: 0 mm; TBQen_C_neighbour_unit_displacement_front: 0 mm; TBQen_C_neighbour_unit_displacement_left: 0 mm; TBQen_C_neighbour_unit_displacement_right: 0 mm
Identity Data - Mark: 158
Mechanical - RSen_M_c01_flow_rate: 16.6862 m3/s; RSen_M_c02_flow_rate: 18.5402 m3/s; RSen_M_c03_flow_rate: 1.85402 m3/s; System Classification: Hydronic Return,Hydronic Supply,Sanitary,Supply Air,Return Air,Supply Air,Power,Controls
Mechanical - Flow - TBQen_M_flow_rate_index: 1; TBQen_M_flow_rate: 18.5402 m3/s; TBQen_M_flow_rate_info: Norm.
Other - Schedule Level: Level: Level 1; ZZZ_V P_c01_plane_Integer: 4; Family: RSen_55_ME_FB_indoor unit - refrigeration - concealed - fresh air intake_daikin: fxsn112a2veb - concealed ceiling unit_daikin_lxwxh 800x1400x245 mm; Family and Type: RSen_55_ME_FB_indoor unit - refrigeration - concealed - fresh air intake_daikin: fxsn112a2veb - concealed ceiling unit_daikin_lxwxh 800x1400x245 mm; Type: RSen_55_ME_FB_indoor unit - refrigeration - concealed - fresh air intake_daikin: fxsn112a2veb - concealed ceiling unit_daikin_lxwxh 800x1400x245 mm; Type Id: RSen_55_ME_FB_indoor unit - refrigeration - concealed - fresh air intake_daikin: fxsn112a2veb - concealed ceiling unit_daikin_lxwxh 800x1400x245 mm; ZZZ_V P_c01_X_Length: 221 mm; ZZZ_V P_c01_Y_Length: -13.5 mm
Phasing - Phase Created: New Construction
Text - RSen_C_content_manual: https://thorbiq.freshdesk.com/support/solutions

# IfcEnergyConversionDevice: vam1500j8veb - heat reclaim ventilation_daikin_lxwxh 1549x1342x731 mm, RSen_57_ME_FB_ventilation - heat reclaim - 8 ducts_daikin:vam1500j8veb - heat reclaim ventilation_daikin_lxwxh 1549x1342x731 mm:1573289
In: Level 1
Type - PredefinedType: AIRHANDLER; Classification: 57.10.10.10 (Uniformat)
Type - Constraints - Default Elevation: 0 mm
Type - Construction - TBQen_C_diameter_type_index: 1; TBQen_C_SOg_ME_02: standard; TBQen_C_diameter_type: OD; TBQen_C_SOg_ME_01: RSen_57_ME_FB_SOg - vam1500j8veb - SH_daikin_tbq: standard
Type - Dimensions - RSen_C_height: 731 mm; RSen_C_length: 1549 mm; RSen_C_width: 1342 mm
Type - Electrical - RSen_E_c01_division_engine: no; RSen_E_c01_load_class: Other; RSen_E_c01_number_of_poles: 1; TBQen_E_c01_power_factor: 1; RSen_E_c01_apparent_power: 548 W; RSen_E_c01_current: 0 A; RSen_E_c01_voltage: 230 V; TBQen_E_c01_power: 548 W
Type - Identity Data - Assembly Code: 57.10.10.10; Description: Heat Recovery; Manufacturer: Daikin Europe N.V.; Model: Ventilation; OmniClass Number: 23.75.35.14; OmniClass Title: Air Handling Units; RSen_C_code_article: VAM1500J8VEB; RSen_C_code_ETIM: Ventilation appliance; RSen_C_code_ETIM_URL: https://prod.etim-international.com/Class/Details?classId=EC000267&classVersion=5; RSen_C_code_gtin: -; RSen_C_code_product_class: VAM-J8; RSen_C_content_creator: © ThorbiQ; RSen_C_content_date_changed: 14/01/2021; RSen_C_content_date_issue: 14/01/2021; RSen_C_content_provider: Daikin Europe N.V.; RSen_C_content_version: 2.0.0; RSen_C_description: Heat Recovery; RSen_C_model: Ventilation; RSen_C_revit_version: 2018; RSen_C_type: Heat reclaim ventilation; RSen_C_type_comments: Indoor Unit; TBQ_I BaseKeynote: 57.10.10.10; TBQen_C_code_product: VAM1500J8; TBQen_C_IFC_version: 2x3; TBQen_C_license: Creative Commons Attribution NoDerivs (CC-ND); TBQen_C_license_info: https://tldrlegal.com/license/creative-commons-attribution-noderivs-(cc-nd)#summary; Type Comments: Indoor Unit; Type Name: vam1500j8veb - heat reclaim ventilation_daikin_lxwxh 1549x1342x731 mm; URL: www.daikineurope.com
Type - Materials and Finishes - RSen_C_material: RSen_x_rgb 255 255 255 T00 pure white_gen
Type - Mechanical - TBQ_I Air flow rate_speed 1: 8.09294 m3/s; TBQ_I Air flow rate_speed 2: 12.5073 m3/s; TBQ_I Air flow rate_speed 3: 14.7144 m3/s
Type - Model Properties - TBQen_C_mounting_ceiling: yes; TBQen_C_mounting_floor: no; TBQen_C_mounting_wall: no
Type - Other - Category: Mechanical Equipment; TBQen_E_c01_yes_no: yes; TBQen_E_c02_yes_no: yes; RSen_M_c01_height: 0 mm; RSen_M_c01_width: 0 mm; RSen_M_c02_height: 0 mm; RSen_M_c02_width: 0 mm; RSen_M_c03_height: 0 mm; RSen_M_c03_width: 0 mm; RSen_M_c04_height: 0 mm; RSen_M_c04_width: 0 mm; RSen_M_c05_height: 0 mm; RSen_M_c05_width: 0 mm; RSen_M_c06_height: 0 mm; RSen_M_c06_width: 0 mm; RSen_M_c07_height: 0 mm; RSen_M_c07_width: 0 mm; RSen_M_c08_height: 0 mm; RSen_M_c08_width: 0 mm; TBQen_M_c01_yes_no: yes; TBQen_M_c02_yes_no: yes; TBQen_M_c03_yes_no: yes; TBQen_M_c04_yes_no: yes; TBQen_M_c05_yes_no: yes; TBQen_M_c06_yes_no: yes; TBQen_M_c07_yes_no: yes; TBQen_M_c08_yes_no: yes; Family Name: RSen_57_ME_FB_ventilation - heat reclaim - 8 ducts_daikin; RSen_E_c01_description: c01_el; RSen_E_c02_description: c02_controls; RSen_M_c01_description: c01_fresh air_outdoor; RSen_M_c01_diameter: 250 mm; RSen_M_c02_description: c02_exhaust air; RSen_M_c02_diameter: 250 mm; RSen_M_c03_description: c03_supply air; RSen_M_c03_diameter: 250 mm; RSen_M_c04_description: c04_return air; RSen_M_c04_diameter: 250 mm; RSen_M_c05_description: c05_fresh air_outdoor; RSen_M_c05_diameter: 250 mm; RSen_M_c06_description: c06_exhaust air; RSen_M_c06_diameter: 250 mm; RSen_M_c07_description: c07_supply air; RSen_M_c07_diameter: 250 mm; RSen_M_c08_description: c08_return air; RSen_M_c08_diameter: 250 mm; TBQen_E_c01_power_factor_state: Lagging; TBQen_E_c01_system_type: Power - Balanced; TBQen_M_c01_flow_configuration: Preset; TBQen_M_c01_flow_direction: In; TBQen_M_c01_loss_method: Not Defined; TBQen_M_c01_shape: Round; TBQen_M_c01_system_classification: Supply Air; TBQen_M_c02_flow_configuration: Preset; TBQen_M_c02_flow_direction: Out; TBQen_M_c02_loss_method: Not Defined; TBQen_M_c02_shape: Round; TBQen_M_c02_system_classification: Exhaust Air; TBQen_M_c03_flow_configuration: Preset; TBQen_M_c03_flow_direction: Out; TBQen_M_c03_loss_method: Not Defined; TBQen_M_c03_shape: Round; TBQen_M_c03_system_classification: Supply Air; TBQen_M_c04_flow_configuration: Preset; TBQen_M_c04_flow_direction: In; TBQen_M_c04_loss_method: Not Defined; TBQen_M_c04_shape: Round; TBQen_M_c04_system_classification: Return Air; TBQen_M_c05_flow_configuration: Preset; TBQen_M_c05_flow_direction: In; TBQen_M_c05_loss_method: Not Defined; TBQen_M_c05_shape: Round; TBQen_M_c05_system_classification: Supply Air; TBQen_M_c06_flow_configuration: Preset; TBQen_M_c06_flow_direction: Out; TBQen_M_c06_loss_method: Not Defined; TBQen_M_c06_shape: Round; TBQen_M_c06_system_classification: Exhaust Air; TBQen_M_c07_flow_configuration: Preset; TBQen_M_c07_flow_direction: Out; TBQen_M_c07_loss_method: Not Defined; TBQen_M_c07_shape: Round; TBQen_M_c07_system_classification: Supply Air; TBQen_M_c08_flow_configuration: Preset; TBQen_M_c08_flow_direction: In; TBQen_M_c08_loss_method: Not Defined; TBQen_M_c08_shape: Round; TBQen_M_c08_system_classification: Return Air
Pset_ManufacturerTypeInformation - Manufacturer: Daikin Europe N.V.
Pset_DistributionFlowElementCommon - Reference: vam1500j8veb - heat reclaim ventilation_daikin_lxwxh 1549x1342x731 mm
Constraints - Level: Level: Level 1; Elevation: 2500 mm; Host: Reference Plane : ceiling
Construction - TBQen_C_alignment_index: 0; TBQen_C_GOg: no; TBQen_C_SOg: yes; TBQen_C_alignment: Center; TBQen_C_suspension_height: 50 mm
Dimensions - Area: 102.387 m2; Volume: 36.6399 m3
Graphics - TBQen_C_clearance_zone: no; TBQen_C_connection_zone: no; TBQen_C_logo: no; TBQen_C_maintenance_zone: no; TBQen_C_neighbour_unit: no; TBQen_C_neighbour_unit_displacement_back: 0 mm; TBQen_C_neighbour_unit_displacement_front: 0 mm; TBQen_C_neighbour_unit_displacement_left: 0 mm; TBQen_C_neighbour_unit_displacement_right: 0 mm
Identity Data - Mark: 104
Mechanical - RSen_M_c01_flow_rate: 8.09294 m3/s; RSen_M_c02_flow_rate: 8.09294 m3/s; RSen_M_c03_flow_rate: 8.09294 m3/s; RSen_M_c04_flow_rate: 8.09294 m3/s; RSen_M_c05_flow_rate: 8.09294 m3/s; RSen_M_c06_flow_rate: 8.09294 m3/s; RSen_M_c07_flow_rate: 8.09294 m3/s; RSen_M_c08_flow_rate: 8.09294 m3/s; System Classification: Return Air,Supply Air,Exhaust Air,Power,Controls,Supply Air
Mechanical - Flow - TBQen_M_flow_rate_index: 0; TBQen_M_flow_rate: 8.09294 m3/s; TBQen_M_flow_rate_info: Low
Other - Schedule Level: Level: Level 1; Family: RSen_57_ME_FB_ventilation - heat reclaim - 8 ducts_daikin: vam1500j8veb - heat reclaim ventilation_daikin_lxwxh 1549x1342x731 mm; Family and Type: RSen_57_ME_FB_ventilation - heat reclaim - 8 ducts_daikin: vam1500j8veb - heat reclaim ventilation_daikin_lxwxh 1549x1342x731 mm; Type: RSen_57_ME_FB_ventilation - heat reclaim - 8 ducts_daikin: vam1500j8veb - heat reclaim ventilation_daikin_lxwxh 1549x1342x731 mm; Type Id: RSen_57_ME_FB_ventilation - heat reclaim - 8 ducts_daikin: vam1500j8veb - heat reclaim ventilation_daikin_lxwxh 1549x1342x731 mm
Phasing - Phase Created: New Construction
Text - RSen_C_content_manual: https://thorbiq.freshdesk.com/support/solutions

# IfcEnergyConversionDevice: vkm100gbmv1 - heat reclaim ventilation, humidification and air processing_daikin_lxwxh 1942x1214x387 mm, RSen_57_ME_FB_ventilation - heat reclaim, humidification and air processing_daikin:vkm100gbmv1 - heat reclaim ventilation, humidification and air processing_daikin_lxwxh 1942x1214x387 mm:1554675
In: Level 1
Type - PredefinedType: AIRHANDLER; Classification: 57.10.10.10 (Uniformat); Material: RSen_x_rgb 255 255 255 T00 pure white_gen
Type - Constraints - Default Elevation: 0 mm
Type - Construction - TBQen_C_diameter_type_index: 1; TBQen_C_SOg_ME_02: standard; TBQen_C_diameter_type: OD; TBQen_C_SOg_ME_01: RSen_57_ME_FB_SOg - vkm100gbmv1 - SH_daikin_tbq: standard
Type - Dimensions - RSen_C_height: 387 mm; RSen_C_length: 1942 mm; RSen_C_width: 1214 mm
Type - Electrical - RSen_E_c01_division_engine: no; RSen_E_c01_load_class: Other; RSen_E_c01_number_of_poles: 1; TBQen_E_c01_power_factor: 1; RSen_E_c01_apparent_power: 410 W; RSen_E_c01_current: 0 A; RSen_E_c01_voltage: 230 V; TBQen_E_c01_power: 410 W
Type - Identity Data - Assembly Code: 57.10.10.10; Description: Heat Recovery; Manufacturer: Daikin Europe N.V.; Model: Ventilation; OmniClass Number: 23.75.35.14; OmniClass Title: Air Handling Units; RSen_C_code_article: VKM100GBMV1; RSen_C_code_ETIM: Ventilation appliance; RSen_C_code_ETIM_URL: https://prod.etim-international.com/Class/Details?classId=EC000267&classVersion=5; RSen_C_code_gtin: -; RSen_C_code_product_class: VKM-GBM; RSen_C_content_creator: © ThorbiQ; RSen_C_content_date_changed: 14/01/2021; RSen_C_content_date_issue: 14/01/2021; RSen_C_content_provider: Daikin Europe N.V.; RSen_C_content_version: 2.0.0; RSen_C_description: Heat Recovery; RSen_C_model: Ventilation; RSen_C_revit_version: 2018; RSen_C_type: Heat reclaim ventilation, humidification and air processing; RSen_C_type_comments: Indoor Unit; TBQ_I BaseKeynote: 57.10.10.10; TBQen_C_code_product: VKM100GBM; TBQen_C_IFC_version: 2x3; TBQen_C_license: Creative Commons Attribution NoDerivs (CC-ND); TBQen_C_license_info: https://tldrlegal.com/license/creative-commons-attribution-noderivs-(cc-nd)#summary; Type Comments: Indoor Unit; Type Name: vkm100gbmv1 - heat reclaim ventilation, humidification and air processing_daikin_lxwxh 1942x1214x387 mm; URL: www.daikineurope.com
Type - Materials and Finishes - RSen_C_material: RSen_x_rgb 255 255 255 T00 pure white_gen
Type - Mechanical - TBQ_I Air flow rate_speed 1: 8.0439 m3/s; TBQ_I Air flow rate_speed 2: 9.31915 m3/s; TBQ_I Air flow rate_speed 3: 9.31915 m3/s
Type - Model Properties - TBQen_C_mounting_ceiling: yes; TBQen_C_mounting_floor: no; TBQen_C_mounting_wall: no
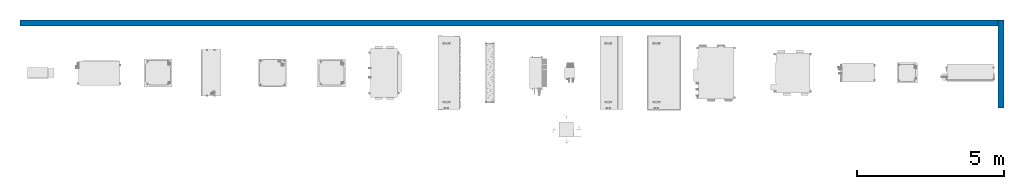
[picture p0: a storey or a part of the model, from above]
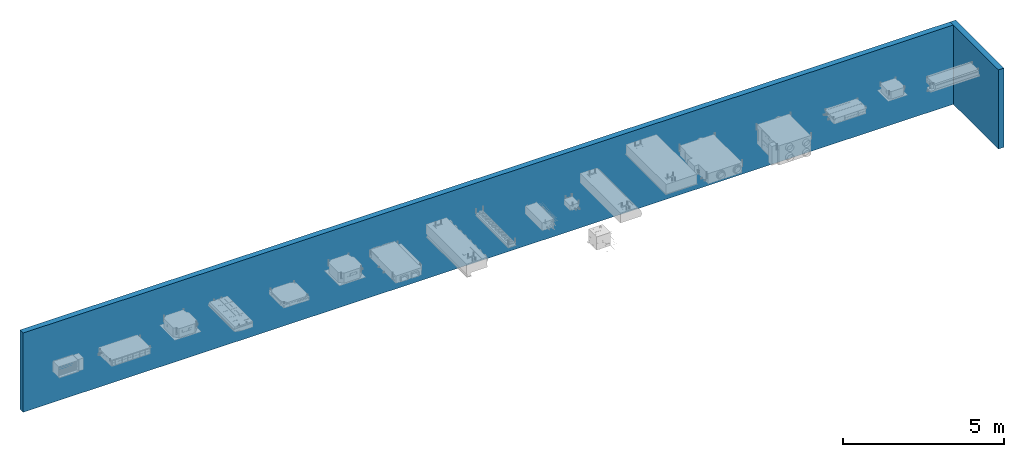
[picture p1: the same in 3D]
Properties of the parts of a building model (IFC2X3), part 3 of 3

# IfcEnergyConversionDevice: vkm100gbmv1 - heat reclaim ventilation, humidification and air processing_daikin_lxwxh 1942x1214x387 mm, RSen_57_ME_FB_ventilation - heat reclaim, humidification and air processing_daikin:vkm100gbmv1 - heat reclaim ventilation, humidification and air processing_daikin_lxwxh 1942x1214x387 mm:1554675
Type - Other - Category: Mechanical Equipment; TBQen_E_c01_yes_no: yes; TBQen_E_c02_yes_no: yes; TBQen_P_c01_yes_no: yes; TBQen_P_c02_yes_no: yes; TBQen_P_c03_yes_no: yes; TBQen_P_c04_yes_no: yes; RSen_M_c01_height: 0 mm; RSen_M_c01_width: 0 mm; RSen_M_c02_height: 0 mm; RSen_M_c02_width: 0 mm; RSen_M_c03_height: 0 mm; RSen_M_c03_width: 0 mm; RSen_M_c04_height: 0 mm; RSen_M_c04_width: 0 mm; TBQen_M_c01_yes_no: yes; TBQen_M_c02_yes_no: yes; TBQen_M_c03_yes_no: yes; TBQen_M_c04_yes_no: yes; Family Name: RSen_57_ME_FB_ventilation - heat reclaim, humidification and air processing_daikin; RSen_E_c01_description: c01_el; RSen_E_c02_description: c02_controls; RSen_M_c01_description: c01_fresh air_outdoor; RSen_M_c01_diameter: 250 mm; RSen_M_c02_description: c02_exhaust air; RSen_M_c02_diameter: 250 mm; RSen_M_c03_description: c03_supply air; RSen_M_c03_diameter: 250 mm; RSen_M_c04_description: c04_return air; RSen_M_c04_diameter: 250 mm; RSen_P_c01_description: c01_liquid piping connection; RSen_P_c01_diameter: 6.35 mm; RSen_P_c02_description: c02_gas piping connection; RSen_P_c02_diameter: 12.7 mm; RSen_P_c03_description: c03_drain piping connection; RSen_P_c03_diameter: 19.1 mm; RSen_P_c04_description: c04_feed water connection; RSen_P_c04_diameter: 6.4 mm; TBQen_E_c01_power_factor_state: Lagging; TBQen_E_c01_system_type: Power - Balanced; TBQen_M_c01_flow_configuration: Preset; TBQen_M_c01_flow_direction: In; TBQen_M_c01_loss_method: Not Defined; TBQen_M_c01_shape: Round; TBQen_M_c01_system_classification: Supply Air; TBQen_M_c02_flow_configuration: Preset; TBQen_M_c02_flow_direction: Out; TBQen_M_c02_loss_method: Not Defined; TBQen_M_c02_shape: Round; TBQen_M_c02_system_classification: Exhaust Air; TBQen_M_c03_flow_configuration: Preset; TBQen_M_c03_flow_direction: Out; TBQen_M_c03_loss_method: Not Defined; TBQen_M_c03_shape: Round; TBQen_M_c03_system_classification: Supply Air; TBQen_M_c04_flow_configuration: Preset; TBQen_M_c04_flow_direction: In; TBQen_M_c04_loss_method: Not Defined; TBQen_M_c04_shape: Round; TBQen_M_c04_system_classification: Return Air; TBQen_P_c01_diameter_calc: 6.4 mm; TBQen_P_c01_flow_configuration: Preset; TBQen_P_c01_flow_direction: In; TBQen_P_c01_loss_method: Not Defined; TBQen_P_c01_system_classification: Hydronic Supply; TBQen_P_c02_diameter_calc: 12.7 mm; TBQen_P_c02_flow_configuration: Preset; TBQen_P_c02_flow_direction: Out; TBQen_P_c02_loss_method: Not Defined; TBQen_P_c02_system_classification: Hydronic Return; TBQen_P_c03_diameter_calc: 19.1 mm; TBQen_P_c03_flow_configuration: Fixture Units; TBQen_P_c03_flow_direction: Out; TBQen_P_c03_loss_method: Not Defined; TBQen_P_c03_system_classification: Sanitary; TBQen_P_c04_diameter_calc: 6.4 mm; TBQen_P_c04_flow_configuration: Preset; TBQen_P_c04_flow_direction: In; TBQen_P_c04_loss_method: Not Defined; TBQen_P_c04_system_classification: Domestic Cold Water
Pset_ManufacturerTypeInformation - Manufacturer: Daikin Europe N.V.
Pset_DistributionFlowElementCommon - Reference: vkm100gbmv1 - heat reclaim ventilation, humidification and air processing_daikin_lxwxh 1942x1214x387 mm
Constraints - Level: Level: Level 1; Elevation: 2500 mm; Host: Reference Plane : ceiling
Construction - TBQen_C_alignment_index: 0; TBQen_C_GOg: no; TBQen_C_SOg: yes; TBQen_C_alignment: Center; TBQen_C_suspension_height: 50 mm
Dimensions - Area: 80.3683 m2; Volume: 20.4287 m3
Graphics - TBQen_C_clearance_zone: no; TBQen_C_connection_zone: no; TBQen_C_logo: no; TBQen_C_maintenance_zone: no; TBQen_C_neighbour_unit: no; TBQen_C_neighbour_unit_displacement_back: 0 mm; TBQen_C_neighbour_unit_displacement_front: 0 mm; TBQen_C_neighbour_unit_displacement_left: 0 mm; TBQen_C_neighbour_unit_displacement_right: 0 mm
Identity Data - Mark: 103
Mechanical - RSen_M_c01_flow_rate: 8.0439 m3/s; RSen_M_c02_flow_rate: 8.0439 m3/s; RSen_M_c03_flow_rate: 8.0439 m3/s; RSen_M_c04_flow_rate: 8.0439 m3/s; RSen_P_c01_volume_flow: 0 m3/s; RSen_P_c02_volume_flow: 0 m3/s; RSen_P_c03_load_value: 0; RSen_P_c04_volume_flow: 0 m3/s; System Classification: Hydronic Return,Hydronic Supply,Sanitary,Return Air,Supply Air,Exhaust Air,Power,Domestic Cold Water,Controls
Mechanical - Flow - TBQen_M_flow_rate: 8.0439 m3/s; TBQen_M_flow_rate_index: 0; TBQen_M_flow_rate_info: Low
Other - Schedule Level: Level: Level 1; Family: RSen_57_ME_FB_ventilation - heat reclaim, humidification and air processing_daikin: vkm100gbmv1 - heat reclaim ventilation, humidification and air processing_daikin_lxwxh 1942x1214x387 mm; Family and Type: RSen_57_ME_FB_ventilation - heat reclaim, humidification and air processing_daikin: vkm100gbmv1 - heat reclaim ventilation, humidification and air processing_daikin_lxwxh 1942x1214x387 mm; Type: RSen_57_ME_FB_ventilation - heat reclaim, humidification and air processing_daikin: vkm100gbmv1 - heat reclaim ventilation, humidification and air processing_daikin_lxwxh 1942x1214x387 mm; Type Id: RSen_57_ME_FB_ventilation - heat reclaim, humidification and air processing_daikin: vkm100gbmv1 - heat reclaim ventilation, humidification and air processing_daikin_lxwxh 1942x1214x387 mm; ZZZ_V P_c01_plane_Integer: 4; ZZZ_V P_c01_X_Length: -367 mm; ZZZ_V P_c01_Y_Length: 59.5 mm
Phasing - Phase Created: New Construction
Text - RSen_C_content_manual: https://thorbiq.freshdesk.com/support/solutions

# IfcFlowFitting: bs16q14av1b - multi branch selector_daikin_lxwxh 1060x430x298 mm, RSen_55_ME_FB_multi branch - bs box_daikin:bs16q14av1b - multi branch selector_daikin_lxwxh 1060x430x298 mm:1185837
In: Level 1
Type - PredefinedType: JUNCTION; Classification: 55.10.10.10 (Uniformat); Material: RSen_x_rgb 255 255 255 T00 pure white_gen
Type - Constraints - Default Elevation: 0 mm
Type - Construction - TBQen_C_diameter_type_index: 1; TBQen_C_SOg_ME_02: standard; TBQen_C_diameter_type: OD; TBQen_C_SOg_ME_01: RSen_55_ME_FB_SOg - bs16q14av1b - SH_daikin_tbq: standard
Type - Dimensions - RSen_C_height: 298 mm; RSen_C_length: 1060 mm; RSen_C_width: 430 mm
Type - Electrical - RSen_E_c01_division_engine: no; RSen_E_c01_load_class: Other; RSen_E_c01_number_of_poles: 1; TBQen_E_c01_power_factor: 1; RSen_E_c01_apparent_power: 368 W; RSen_E_c01_current: 1.6 A; RSen_E_c01_voltage: 230 V; TBQen_E_c01_power: 0 W
Type - Identity Data - Assembly Code: 55.10.10.10; Description: Heat Recovery; Manufacturer: Daikin Europe N.V.; Model: VRV BS; OmniClass Number: 23.75.70.11.11; OmniClass Title: Distribution Collectors; RSen_C_code_article: BS16Q14AV1B; RSen_C_code_ETIM: Accessories for airconditioning; RSen_C_code_ETIM_URL: https://prod.etim-international.com/Class/Details?classId=EC011603&classVersion=3; RSen_C_code_gtin: -; RSen_C_code_product_class: BS-Q14AV1B; RSen_C_content_creator: © ThorbiQ; RSen_C_content_date_changed: 14/01/2021; RSen_C_content_date_issue: 14/01/2021; RSen_C_content_provider: Daikin Europe N.V.; RSen_C_content_version: 2.0.0; RSen_C_description: Heat Recovery; RSen_C_model: VRV BS; RSen_C_revit_version: 2018; RSen_C_type: Multi branch selector; RSen_C_type_comments: Accessory; TBQ_I BaseKeynote: 55.10.10.10; TBQen_C_code_product: BS16Q14A; TBQen_C_IFC_version: 2x3; TBQen_C_license: Creative Commons Attribution NoDerivs (CC-ND); TBQen_C_license_info: https://tldrlegal.com/license/creative-commons-attribution-noderivs-(cc-nd)#summary; Type Comments: Accessory; Type Name: bs16q14av1b - multi branch selector_daikin_lxwxh 1060x430x298 mm; URL: www.daikineurope.com
Type - Materials and Finishes - RSen_C_material: RSen_x_rgb 255 255 255 T00 pure white_gen
Type - Model Properties - TBQen_C_mounting_ceiling: yes; TBQen_C_mounting_floor: no; TBQen_C_mounting_wall: no
Type - Other - Category: Mechanical Equipment; TBQen_E_c01_yes_no: yes; TBQen_P_c01_yes_no: yes; TBQen_P_c02_yes_no: yes; TBQen_P_c03_yes_no: yes; TBQen_P_c04_yes_no: yes; Family Name: RSen_55_ME_FB_multi branch - bs box_daikin; RSen_E_c01_description: c01_el; RSen_P_c01_description: c01_outdoor unit suction gas pipe connection; RSen_P_c01_diameter: 34.9 mm; RSen_P_c02_description: c02_outdoor unit HP/LP gas pipe connection; RSen_P_c02_diameter: 28.6 mm; RSen_P_c03_description: c03_outdoor unit liquid pipe connection; RSen_P_c03_diameter: 19.1 mm; RSen_P_c04_description: c04_drain piping connection; RSen_P_c04_diameter: 26 mm; RSen_P_c05_description: c05_Indoor unit liquid pipe connection; RSen_P_c05_diameter: 9.5 mm; RSen_P_c06_description: c06_Indoor unit gas pipe connection; RSen_P_c06_diameter: 15.9 mm; RSen_P_c07_description: c07_Indoor unit liquid pipe connection; RSen_P_c07_diameter: 9.5 mm; RSen_P_c08_description: c08_Indoor unit gas pipe connection; RSen_P_c08_diameter: 15.9 mm; RSen_P_c09_description: c09_Indoor unit liquid pipe connection; RSen_P_c09_diameter: 9.5 mm; RSen_P_c10_description: c10_Indoor unit gas pipe connection; RSen_P_c10_diameter: 15.9 mm; RSen_P_c11_description: c11_Indoor unit liquid pipe connection; RSen_P_c11_diameter: 9.5 mm; RSen_P_c12_description: c12_Indoor unit gas pipe connection; RSen_P_c12_diameter: 15.9 mm; RSen_P_c13_description: c13_Indoor unit liquid pipe connection; RSen_P_c13_diameter: 9.5 mm; RSen_P_c14_description: c14_Indoor unit gas pipe connection; RSen_P_c14_diameter: 15.9 mm; RSen_P_c15_description: c15_Indoor unit liquid pipe connection; RSen_P_c15_diameter: 9.5 mm; RSen_P_c16_description: c16_Indoor unit gas pipe connection; RSen_P_c16_diameter: 15.9 mm; RSen_P_c17_description: c17_Indoor unit liquid pipe connection; RSen_P_c17_diameter: 9.5 mm; RSen_P_c18_description: c18_Indoor unit gas pipe connection; RSen_P_c18_diameter: 15.9 mm; RSen_P_c19_description: c19_Indoor unit liquid pipe connection; RSen_P_c19_diameter: 9.5 mm; RSen_P_c20_description: c20_Indoor unit gas pipe connection; RSen_P_c20_diameter: 15.9 mm; RSen_P_c21_description: c21_Indoor unit liquid pipe connection; RSen_P_c21_diameter: 9.5 mm; RSen_P_c22_description: c22_Indoor unit gas pipe connection; RSen_P_c22_diameter: 15.9 mm; RSen_P_c23_description: c23_Indoor unit liquid pipe connection; RSen_P_c23_diameter: 9.5 mm; RSen_P_c24_description: c24_Indoor unit gas pipe connection; RSen_P_c24_diameter: 15.9 mm; RSen_P_c25_description: c25_Indoor unit liquid pipe connection; RSen_P_c25_diameter: 9.5 mm; RSen_P_c26_description: c26_Indoor unit gas pipe connection; RSen_P_c26_diameter: 15.9 mm; RSen_P_c27_description: c27_Indoor unit liquid pipe connection; RSen_P_c27_diameter: 9.5 mm; RSen_P_c28_description: c28_Indoor unit gas pipe connection; RSen_P_c28_diameter: 15.9 mm; RSen_P_c29_description: c29_Indoor unit liquid pipe connection; RSen_P_c29_diameter: 9.5 mm; RSen_P_c30_description: c30_Indoor unit gas pipe connection; RSen_P_c30_diameter: 15.9 mm; RSen_P_c31_description: c31_Indoor unit liquid pipe connection; RSen_P_c31_diameter: 9.5 mm; RSen_P_c32_description: c32_Indoor unit gas pipe connection; RSen_P_c32_diameter: 15.9 mm; RSen_P_c33_description: c33_Indoor unit liquid pipe connection; RSen_P_c33_diameter: 9.5 mm; RSen_P_c34_description: c34_Indoor unit gas pipe connection; RSen_P_c34_diameter: 15.9 mm; RSen_P_c35_description: c35_Indoor unit liquid pipe connection; RSen_P_c35_diameter: 9.5 mm; RSen_P_c36_description: c36_Indoor unit gas pipe connection; RSen_P_c36_diameter: 15.9 mm; TBQen_E_c01_power_factor_state: Lagging; TBQen_E_c01_system_type: Power - Balanced; TBQen_P_c01_diameter_calc: 34.9 mm; TBQen_P_c01_flow_configuration: Preset; TBQen_P_c01_flow_direction: Out; TBQen_P_c01_loss_method: Not Defined; TBQen_P_c01_system_classification: Hydronic Return; TBQen_P_c02_diameter_calc: 28.6 mm; TBQen_P_c02_flow_configuration: Preset; TBQen_P_c02_flow_direction: Bidirectional; TBQen_P_c02_loss_method: Not Defined; TBQen_P_c02_system_classification: Global; TBQen_P_c03_diameter_calc: 19.1 mm; TBQen_P_c03_flow_configuration: Preset; TBQen_P_c03_flow_direction: In; TBQen_P_c03_loss_method: Not Defined; TBQen_P_c03_system_classification: Hydronic Supply; TBQen_P_c04_diameter_calc: 26 mm; TBQen_P_c04_flow_configuration: Fixture Units; TBQen_P_c04_flow_direction: Out; TBQen_P_c04_loss_method: Not Defined; TBQen_P_c04_system_classification: Sanitary; TBQen_P_c05_diameter_calc: 9.5 mm; TBQen_P_c06_diameter_calc: 15.9 mm; TBQen_P_c07_diameter_calc: 9.5 mm; TBQen_P_c08_diameter_calc: 15.9 mm; TBQen_P_c09_diameter_calc: 9.5 mm; TBQen_P_c10_diameter_calc: 15.9 mm; TBQen_P_c11_diameter_calc: 9.5 mm; TBQen_P_c12_diameter_calc: 15.9 mm; TBQen_P_c13_diameter_calc: 9.5 mm; TBQen_P_c14_diameter_calc: 15.9 mm; TBQen_P_c15_diameter_calc: 9.5 mm; TBQen_P_c16_diameter_calc: 15.9 mm; TBQen_P_c17_diameter_calc: 9.5 mm; TBQen_P_c18_diameter_calc: 15.9 mm; TBQen_P_c19_diameter_calc: 9.5 mm; TBQen_P_c20_diameter_calc: 15.9 mm; TBQen_P_c21_diameter_calc: 9.5 mm; TBQen_P_c22_diameter_calc: 15.9 mm; TBQen_P_c23_diameter_calc: 9.5 mm; TBQen_P_c24_diameter_calc: 15.9 mm; TBQen_P_c25_diameter_calc: 9.5 mm; TBQen_P_c26_diameter_calc: 15.9 mm; TBQen_P_c27_diameter_calc: 9.5 mm; TBQen_P_c28_diameter_calc: 15.9 mm; TBQen_P_c29_diameter_calc: 9.5 mm; TBQen_P_c30_diameter_calc: 15.9 mm; TBQen_P_c31_diameter_calc: 9.5 mm; TBQen_P_c32_diameter_calc: 15.9 mm; TBQen_P_c33_diameter_calc: 9.5 mm; TBQen_P_c34_diameter_calc: 15.9 mm; TBQen_P_c35_diameter_calc: 9.5 mm; TBQen_P_c36_diameter_calc: 15.9 mm
Pset_ManufacturerTypeInformation - Manufacturer: Daikin Europe N.V.
Pset_DistributionFlowElementCommon - Reference: bs16q14av1b - multi branch selector_daikin_lxwxh 1060x430x298 mm
Constraints - Level: Level: Level 1; Elevation: 2500 mm; Host: Reference Plane : ceiling
Construction - TBQen_C_alignment_index: 0; TBQen_C_GOg: no; TBQen_C_SOg: yes; TBQen_C_alignment: Center; TBQen_C_suspension_height: 120 mm
Dimensions - Area: 20.8697 m2; Volume: 4.07015 m3
Graphics - TBQen_C_clearance_zone: no; TBQen_C_connection_zone: no; TBQen_C_logo: no; TBQen_C_maintenance_zone: no; TBQen_C_neighbour_unit: no; TBQen_C_neighbour_unit_displacement_back: 0 mm; TBQen_C_neighbour_unit_displacement_front: 0 mm; TBQen_C_neighbour_unit_displacement_left: 0 mm; TBQen_C_neighbour_unit_displacement_right: 0 mm
Identity Data - Mark: 62
Mechanical - RSen_P_c01_volume_flow: 0 m3/s; RSen_P_c02_volume_flow: 0 m3/s; RSen_P_c03_volume_flow: 0 m3/s; RSen_P_c04_load_value: 0; RSen_P_c05_volume_flow: 0 m3/s; RSen_P_c06_volume_flow: 0 m3/s; RSen_P_c07_volume_flow: 0 m3/s; RSen_P_c08_volume_flow: 0 m3/s; RSen_P_c09_volume_flow: 0 m3/s; RSen_P_c10_volume_flow: 0 m3/s; RSen_P_c11_volume_flow: 0 m3/s; RSen_P_c12_volume_flow: 0 m3/s; RSen_P_c13_volume_flow: 0 m3/s; RSen_P_c14_volume_flow: 0 m3/s; RSen_P_c15_volume_flow: 0 m3/s; RSen_P_c16_volume_flow: 0 m3/s; RSen_P_c17_volume_flow: 0 m3/s; RSen_P_c18_volume_flow: 0 m3/s; RSen_P_c19_volume_flow: 0 m3/s; RSen_P_c20_volume_flow: 0 m3/s; RSen_P_c21_volume_flow: 0 m3/s; RSen_P_c22_volume_flow: 0 m3/s; RSen_P_c23_volume_flow: 0 m3/s; RSen_P_c24_volume_flow: 0 m3/s; RSen_P_c25_volume_flow: 0 m3/s; RSen_P_c26_volume_flow: 0 m3/s; RSen_P_c27_volume_flow: 0 m3/s; RSen_P_c28_volume_flow: 0 m3/s; RSen_P_c29_volume_flow: 0 m3/s; RSen_P_c30_volume_flow: 0 m3/s; RSen_P_c31_volume_flow: 0 m3/s; RSen_P_c32_volume_flow: 0 m3/s; RSen_P_c33_volume_flow: 0 m3/s; RSen_P_c34_volume_flow: 0 m3/s; RSen_P_c35_volume_flow: 0 m3/s; RSen_P_c36_volume_flow: 0 m3/s; System Classification: Undefined,Hydronic Return,Hydronic Supply,Power,Sanitary,Hydronic Return,Hydronic Supply
Other - Schedule Level: Level: Level 1; Family: RSen_55_ME_FB_multi branch - bs box_daikin: bs16q14av1b - multi branch selector_daikin_lxwxh 1060x430x298 mm; Family and Type: RSen_55_ME_FB_multi branch - bs box_daikin: bs16q14av1b - multi branch selector_daikin_lxwxh 1060x430x298 mm; Type: RSen_55_ME_FB_multi branch - bs box_daikin: bs16q14av1b - multi branch selector_daikin_lxwxh 1060x430x298 mm; Type Id: RSen_55_ME_FB_multi branch - bs box_daikin: bs16q14av1b - multi branch selector_daikin_lxwxh 1060x430x298 mm
Phasing - Phase Created: New Construction
Text - RSen_C_content_manual: https://thorbiq.freshdesk.com/support/solutions

# IfcFlowFitting: bs1q25a7v1b - individual branch selector_daikin_lxwxh 388x326x207 mm, RSen_55_ME_FB_individual branch - bs box_daikin:bs1q25a7v1b - individual branch selector_daikin_lxwxh 388x326x207 mm:1185836
In: Level 1
Type - PredefinedType: JUNCTION; Classification: 55.10.10.10 (Uniformat); Material: RSen_x_rgb 255 255 255 T00 pure white_gen
Type - Constraints - Default Elevation: 0 mm
Type - Construction - TBQen_C_diameter_type_index: 1; TBQen_C_SOg_ME_02: standard; TBQen_C_diameter_type: OD; TBQen_C_SOg_ME_01: RSen_55_ME_FB_SOg - bs1q25a7v1b - SH_daikin_tbq: standard
Type - Dimensions - RSen_C_height: 207 mm; RSen_C_length: 388 mm; RSen_C_width: 326 mm
Type - Electrical - RSen_E_c01_division_engine: no; RSen_E_c01_load_class: Other; RSen_E_c01_number_of_poles: 1; TBQen_E_c01_power_factor: 1; RSen_E_c01_apparent_power: 23 W; RSen_E_c01_current: 0.1 A; RSen_E_c01_voltage: 230 V; TBQen_E_c01_power: 0 W
Type - Identity Data - Assembly Code: 55.10.10.10; Description: Heat Recovery; Manufacturer: Daikin Europe N.V.; Model: VRV BS; OmniClass Number: 23.75.70.11.11; OmniClass Title: Distribution Collectors; RSen_C_code_article: BS1Q25A7V1B; RSen_C_code_ETIM: Accessories for airconditioning; RSen_C_code_ETIM_URL: https://prod.etim-international.com/Class/Details?classId=EC011603&classVersion=3; RSen_C_code_gtin: -; RSen_C_code_product_class: BS1Q-A; RSen_C_content_creator: © ThorbiQ; RSen_C_content_date_changed: 14/01/2021; RSen_C_content_date_issue: 14/01/2021; RSen_C_content_provider: Daikin Europe N.V.; RSen_C_content_version: 2.0.0; RSen_C_description: Heat Recovery; RSen_C_model: VRV BS; RSen_C_revit_version: 2018; RSen_C_type: Individual branch selector; RSen_C_type_comments: Accessory; TBQ_I BaseKeynote: 55.10.10.10; TBQen_C_code_product: BS1Q25A; TBQen_C_IFC_version: 2x3; TBQen_C_license: Creative Commons Attribution NoDerivs (CC-ND); TBQen_C_license_info: https://tldrlegal.com/license/creative-commons-attribution-noderivs-(cc-nd)#summary; Type Comments: Accessory; Type Name: bs1q25a7v1b - individual branch selector_daikin_lxwxh 388x326x207 mm; URL: www.daikineurope.com
Type - Materials and Finishes - RSen_C_material: RSen_x_rgb 255 255 255 T00 pure white_gen
Type - Model Properties - TBQen_C_mounting_ceiling: yes; TBQen_C_mounting_floor: no; TBQen_C_mounting_wall: no
Type - Other - Category: Mechanical Equipment; TBQen_E_c01_yes_no: yes; TBQen_P_c01_yes_no: yes; TBQen_P_c02_yes_no: yes; Family Name: RSen_55_ME_FB_individual branch - bs box_daikin; RSen_E_c01_description: c01_el; RSen_P_c01_description: c01_suction gas pipe connection; RSen_P_c01_diameter: 22.2 mm; RSen_P_c02_description: c02_HP/LP gas pipe connection; RSen_P_c02_diameter: 19.1 mm; RSen_P_c03_description: c03_liquid pipe connection; RSen_P_c03_diameter: 9.5 mm; RSen_P_c04_description: c04_liquid pipe connection; RSen_P_c04_diameter: 9.5 mm; RSen_P_c05_description: c05_gas pipe connection; RSen_P_c05_diameter: 22.2 mm; TBQen_E_c01_power_factor_state: Lagging; TBQen_E_c01_system_type: Power - Balanced; TBQen_P_c01_diameter_calc: 22.2 mm; TBQen_P_c01_flow_configuration: Preset; TBQen_P_c01_flow_direction: Out; TBQen_P_c01_loss_method: Not Defined; TBQen_P_c01_system_classification: Hydronic Return; TBQen_P_c02_diameter_calc: 19.1 mm; TBQen_P_c02_flow_configuration: Preset; TBQen_P_c02_flow_direction: Bidirectional; TBQen_P_c02_loss_method: Not Defined; TBQen_P_c02_system_classification: Global; TBQen_P_c03_diameter_calc: 9.5 mm; TBQen_P_c03_flow_configuration: Preset; TBQen_P_c03_flow_direction: In; TBQen_P_c03_loss_method: Not Defined; TBQen_P_c03_system_classification: Hydronic Supply; TBQen_P_c03_yes_no: yes; TBQen_P_c04_diameter_calc: 9.5 mm; TBQen_P_c04_flow_configuration: Calculated; TBQen_P_c04_flow_direction: Out; TBQen_P_c04_loss_method: Not Defined; TBQen_P_c04_system_classification: Hydronic Supply; TBQen_P_c04_yes_no: yes; TBQen_P_c05_diameter_calc: 22.2 mm; TBQen_P_c05_flow_configuration: Calculated; TBQen_P_c05_flow_direction: In; TBQen_P_c05_loss_method: Not Defined; TBQen_P_c05_system_classification: Hydronic Return; TBQen_P_c05_yes_no: yes
Pset_ManufacturerTypeInformation - Manufacturer: Daikin Europe N.V.
Pset_DistributionFlowElementCommon - Reference: bs1q25a7v1b - individual branch selector_daikin_lxwxh 388x326x207 mm
Constraints - Level: Level: Level 1; Elevation: 2500 mm; Host: Reference Plane : ceiling
Construction - TBQen_C_alignment_index: 0; TBQen_C_GOg: no; TBQen_C_SOg: yes; TBQen_C_alignment: Center; TBQen_C_suspension_height: 85 mm
Dimensions - Area: 6.51436 m2; Volume: 0.768278 m3
Graphics - TBQen_C_clearance_zone: no; TBQen_C_connection_zone: no; TBQen_C_logo: no; TBQen_C_maintenance_zone: no; TBQen_C_neighbour_unit: no; TBQen_C_neighbour_unit_displacement_back: 0 mm; TBQen_C_neighbour_unit_displacement_front: 0 mm; TBQen_C_neighbour_unit_displacement_left: 0 mm; TBQen_C_neighbour_unit_displacement_right: 0 mm
Identity Data - Mark: 61
Mechanical - RSen_P_c01_volume_flow: 0 m3/s; RSen_P_c02_volume_flow: 0 m3/s; RSen_P_c03_volume_flow: 0 m3/s; RSen_P_c04_volume_flow: 0 m3/s; RSen_P_c05_volume_flow: 0 m3/s; System Classification: Undefined,Hydronic Return,Hydronic Supply,Power,Hydronic Supply,Hydronic Return
Other - Schedule Level: Level: Level 1; Family: RSen_55_ME_FB_individual branch - bs box_daikin: bs1q25a7v1b - individual branch selector_daikin_lxwxh 388x326x207 mm; Family and Type: RSen_55_ME_FB_individual branch - bs box_daikin: bs1q25a7v1b - individual branch selector_daikin_lxwxh 388x326x207 mm; Type: RSen_55_ME_FB_individual branch - bs box_daikin: bs1q25a7v1b - individual branch selector_daikin_lxwxh 388x326x207 mm; Type Id: RSen_55_ME_FB_individual branch - bs box_daikin: bs1q25a7v1b - individual branch selector_daikin_lxwxh 388x326x207 mm; ZZZ_V P_c01_plane_Integer: 5; ZZZ_V P_c01_X_Length: 116 mm; ZZZ_V P_c01_Y_Length: 6.5 mm
Phasing - Phase Created: New Construction
Text - RSen_C_content_manual: https://thorbiq.freshdesk.com/support/solutions

# IfcFlowTerminal: standard, RSen_57_AIR_FB_SOg - cyqs200dk100rbn - SH_daikin_tbq:standard:1752363
In: Level 1
Type - Material: RSen_x_rgb 255 255 255 T00 pure white_gen, RSen_x_rgb 0 0 0 T30 aluminium rectangular canvas_gen
Type - Constraints - Default Elevation: 1219.2 mm; TBQ SOg: yes
Type - Dimensions - TBQ Height: 101.5 mm; TBQ Length: 2048 mm; TBQ Width: 308 mm
Type - Identity Data - Manufacturer: Daikin Europe N.V.; Type Name: standard
Type - Materials and Finishes - TBQ Material 01: RSen_x_rgb 255 255 255 T00 pure white_gen; TBQ Material 02: RSen_x_rgb 0 0 0 T30 aluminium rectangular canvas_gen
Type - Other - Category: Air Terminals; Family Name: RSen_57_AIR_FB_SOg - cyqs200dk100rbn - SH_daikin_tbq
Pset_ManufacturerTypeInformation - Manufacturer: Daikin Europe N.V.
Pset_DistributionFlowElementCommon - Reference: standard
Constraints - Moves With Nearby Elements: no
Dimensions - Area: 1.91761 m2; Volume: 0.0061394 m3
Identity Data - Mark: 5
Other - Family: RSen_57_AIR_FB_SOg - cyqs200dk100rbn - SH_daikin_tbq: standard; Family and Type: RSen_57_AIR_FB_SOg - cyqs200dk100rbn - SH_daikin_tbq: standard; Type: RSen_57_AIR_FB_SOg - cyqs200dk100rbn - SH_daikin_tbq: standard; Type Id: RSen_57_AIR_FB_SOg - cyqs200dk100rbn - SH_daikin_tbq: standard
Phasing - Phase Created: New Construction

# IfcWallStandardCase: Basic Wall:Wall 1 (2)
In: Level 1
Type - PredefinedType: STANDARD; Material: RSen_x_rgb 192 192 192 T00 silver_gen 200 mm
Type - Analytical Properties - Absorptance: 0.1; Roughness: 1
Type - Construction - Function: Exterior; Width: 200 mm; Wrapping at Inserts: Do not wrap
Type - Graphics - Coarse Scale Fill Color: 0
Type - Identity Data - Type Name: Wall 1
Type - Other - Category: Walls; Family Name: Basic Wall
Constraints - Base Constraint: Level: Level 1; Base Extension Distance: 0 mm; Base is Attached: no; Base Offset: 0 mm; Location Line: Wall Centerline; Related to Mass: no; Room Bounding: yes; Top Extension Distance: 0 mm; Top is Attached: no; Top Offset: 0 mm; Unconnected Height: 3000 mm
Other - Family: Basic Wall: Wall 1; Family and Type: Basic Wall: Wall 1; Type: Basic Wall: Wall 1; Type Id: Basic Wall: Wall 1
Phasing - Phase Created: New Construction
Structural - Enable Analytical Model: no; Structural: no; Structural Usage: Non-bearing
Pset_WallCommon - Reference: Wall 1; LoadBearing: no; ExtendToStructure: no; IsExternal: yes
Name (Basic Wall:Wall 1:...) | Area (m2) | Length (mm) | Volume (m3)
87925 | 9 | 2900 | 1.8
390720 | 99.9 | 33400 | 19.98
